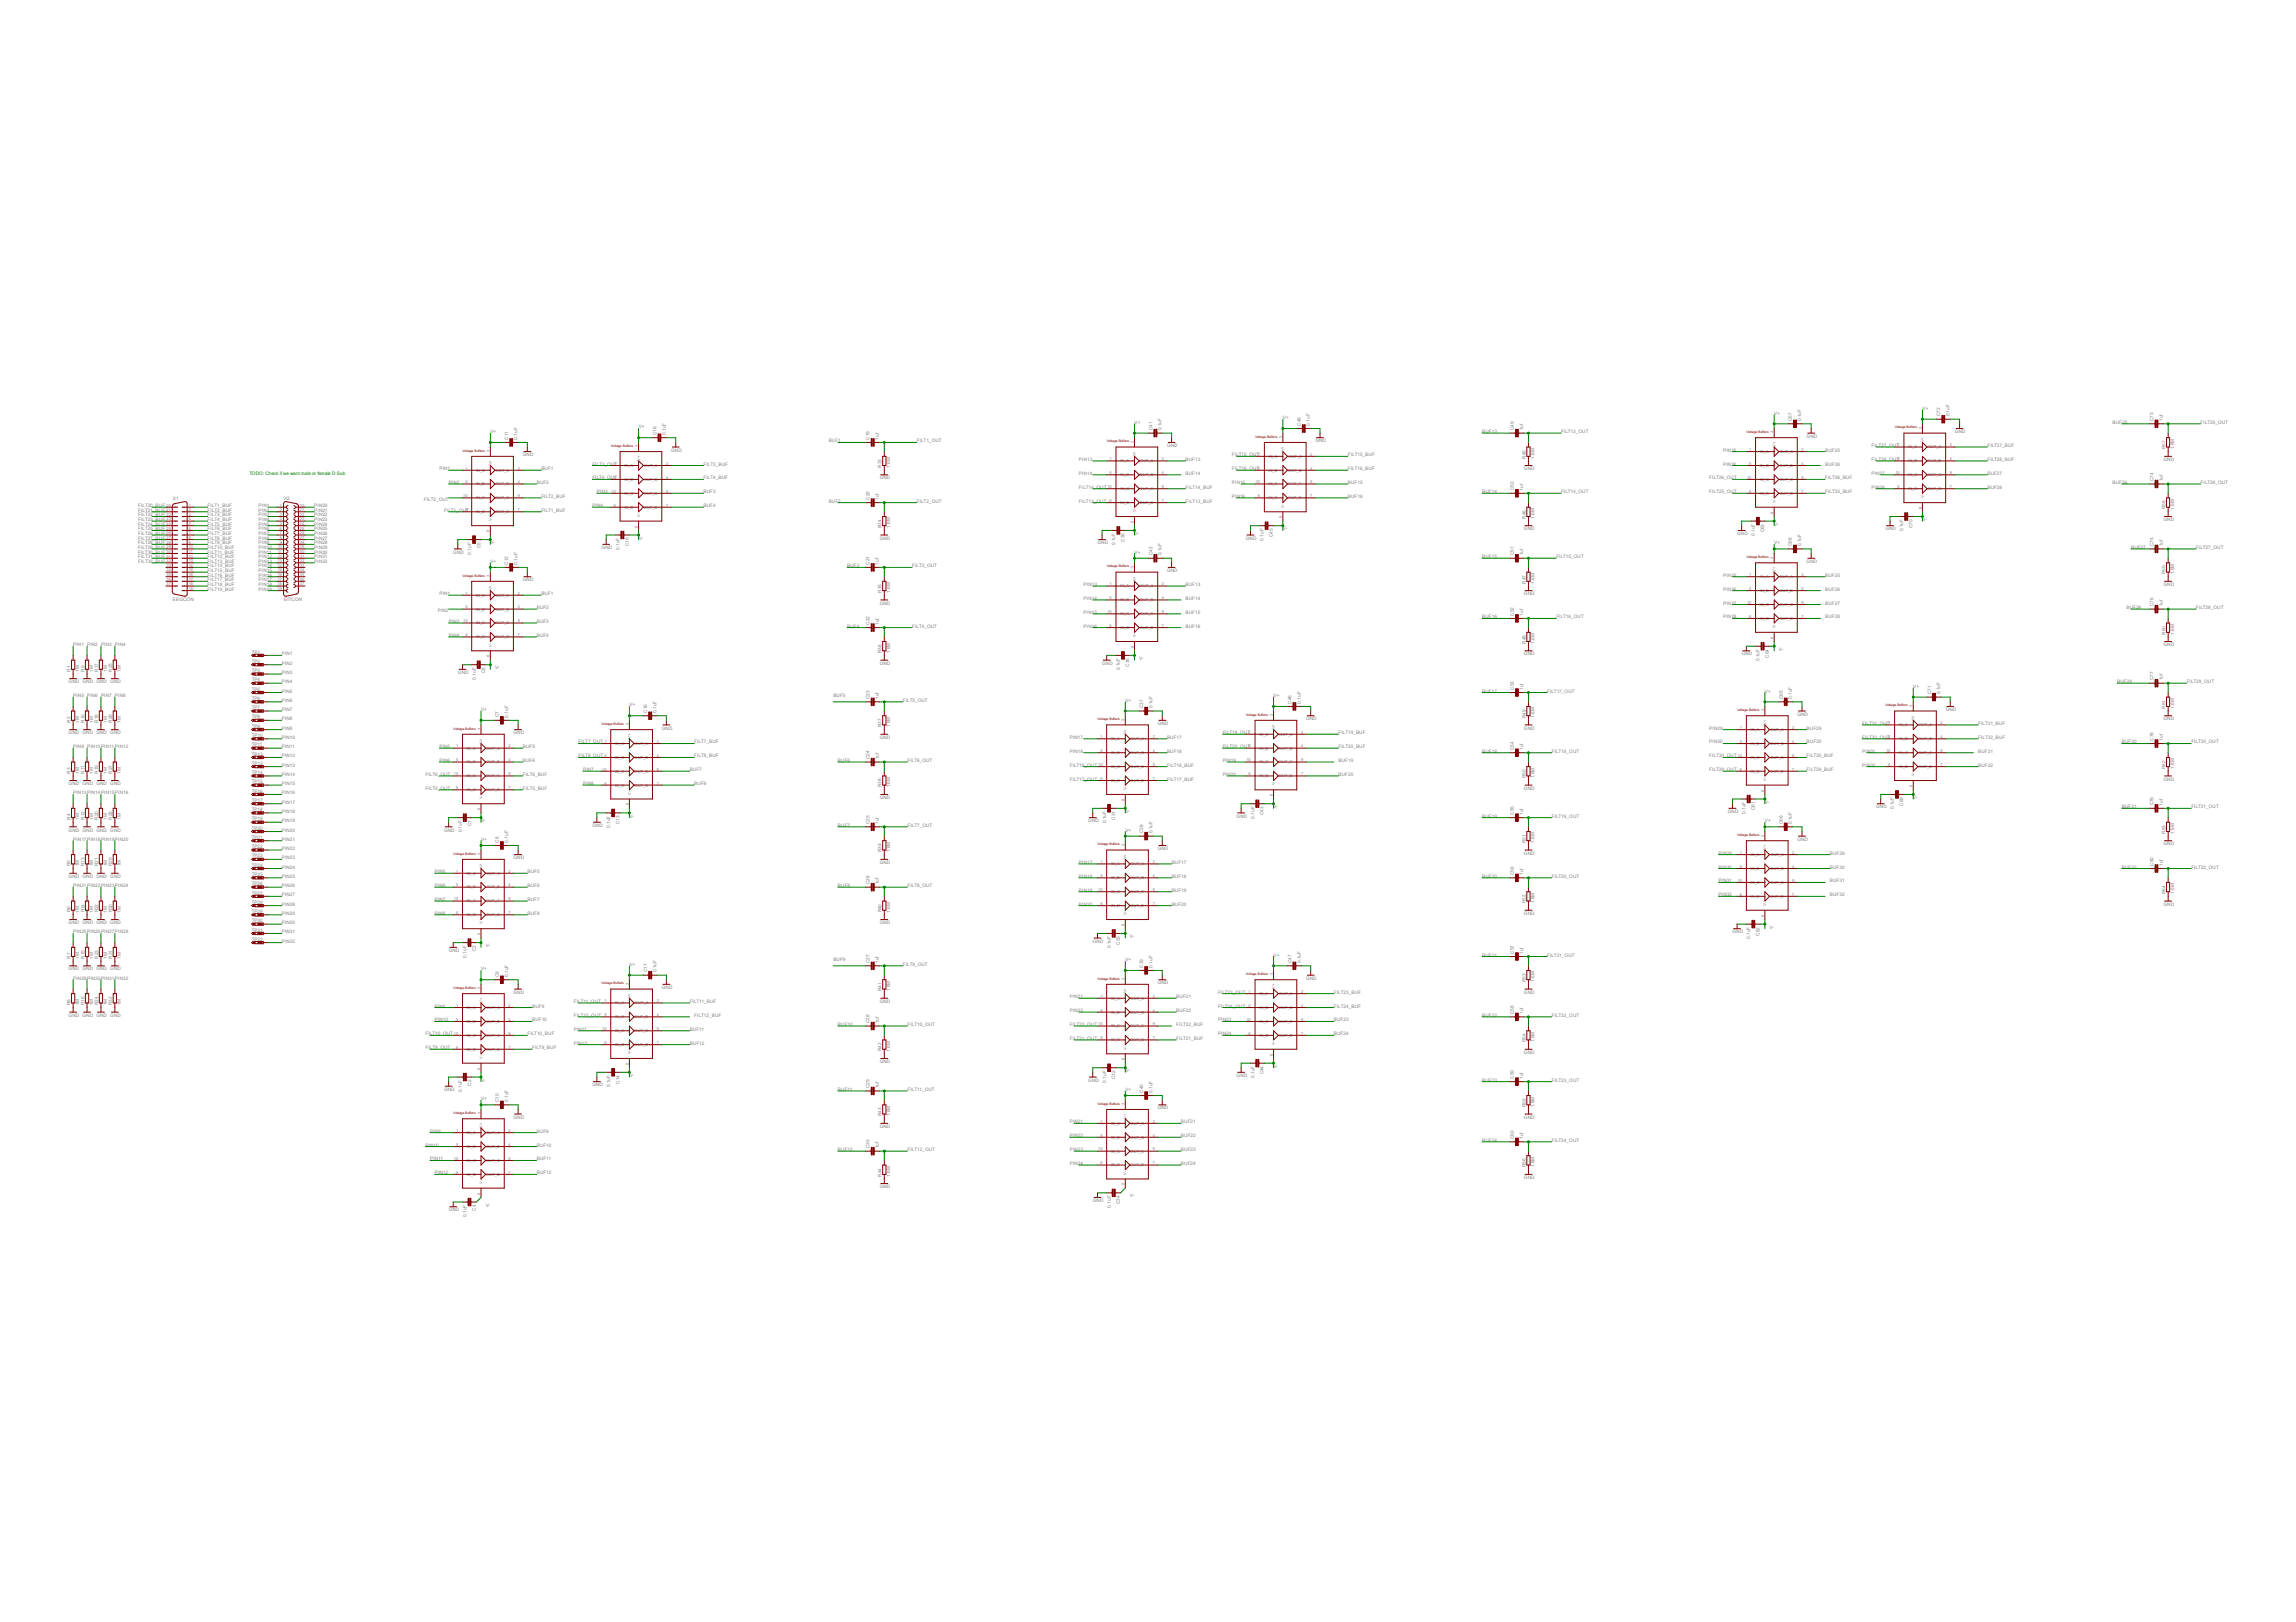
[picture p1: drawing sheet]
<svg xmlns="http://www.w3.org/2000/svg" width="297mm" height="210mm" viewBox="0 0 297 210" stroke-linecap="round" stroke-linejoin="round" font-family="sans-serif">
<defs><g id="words">
<g font-size=".7" fill="#808080">
<text x="229.5" y="53.7">V+</text>
<text x="248.7" y="53.1">V+</text>
<text x="251" y="53.9" transform="rotate(-90 251 53.9)">C72</text>
<text x="252.2" y="53.9" transform="rotate(-90 252.2 53.9)">0.1uF</text>
<text x="63.4" y="56">V+</text>
<text x="65.7" y="56.9" transform="rotate(-90 65.7 56.9)">C11</text>
<text x="66.9" y="56.9" transform="rotate(-90 66.9 56.9)">0.1uF</text>
<text x="67.6" y="59">GND</text>
<text x="82.6" y="55.4">V+</text>
<text x="84.9" y="56.3" transform="rotate(-90 84.9 56.3)">C18</text>
<text x="86.1" y="56.3" transform="rotate(-90 86.1 56.3)">0.1uF</text>
<text x="86.8" y="58.4">GND</text>
<text x="107.2" y="57.2">BUF1</text>
<text x="112.5" y="56.9" transform="rotate(-90 112.5 56.9)">C19</text>
<text x="113.7" y="56.9" transform="rotate(-90 113.7 56.9)">1uf</text>
<text x="118.6" y="57.2">FILT1_OUT</text>
<text x="139.6" y="59.6">PIN13</text>
<text x="146.8" y="54.8">V+</text>
<text x="149.1" y="55.7" transform="rotate(-90 149.1 55.7)">C41</text>
<text x="150.3" y="55.7" transform="rotate(-90 150.3 55.7)">0.1uF</text>
<text x="151" y="57.8">GND</text>
<text x="153.4" y="59.6">BUF13</text>
<text x="159.4" y="59">FILT15_OUT</text>
<text x="166" y="54.2">V+</text>
<text x="168.3" y="55.1" transform="rotate(-90 168.3 55.1)">C48</text>
<text x="169.5" y="55.1" transform="rotate(-90 169.5 55.1)">0.1uF</text>
<text x="170.2" y="57.2">GND</text>
<text x="174.4" y="59">FILT15_BUF</text>
<text x="191.8" y="56">BUF13</text>
<text x="195.9" y="55.7" transform="rotate(-90 195.9 55.7)">C49</text>
<text x="197.1" y="55.7" transform="rotate(-90 197.1 55.7)">1uf</text>
<text x="197.4" y="59.3" transform="rotate(-90 197.4 59.3)">R45</text>
<text x="198.5" y="59.3" transform="rotate(-90 198.5 59.3)">1.6M</text>
<text x="202" y="56">FILT13_OUT</text>
<text x="222.9" y="58.4">PIN25</text>
<text x="231.8" y="54.5" transform="rotate(-90 231.8 54.5)">C67</text>
<text x="233" y="54.5" transform="rotate(-90 233 54.5)">0.1uF</text>
<text x="233.7" y="56.6">GND</text>
<text x="236.1" y="58.4">BUF25</text>
<text x="242.1" y="57.8">FILT27_OUT</text>
<text x="242.1" y="59.6">FILT28_OUT</text>
<text x="252.9" y="56">GND</text>
<text x="257.1" y="57.8">FILT27_BUF</text>
<text x="257.1" y="59.6">FILT28_BUF</text>
<text x="273.3" y="54.8">BUF25</text>
<text x="278.6" y="54.5" transform="rotate(-90 278.6 54.5)">C73</text>
<text x="279.8" y="54.5" transform="rotate(-90 279.8 54.5)">1uf</text>
<text x="279.9" y="59.6">GND</text>
<text x="280.1" y="58.1" transform="rotate(-90 280.1 58.1)">R57</text>
<text x="281.3" y="58.1" transform="rotate(-90 281.3 58.1)">1.6M</text>
<text x="284.7" y="54.8">FILT25_OUT</text>
<text x="17.9" y="65.6">FILT20_BUF</text>
<text x="22.4" y="64.7">X1</text>
<text x="26.9" y="65.6">FILT1_BUF</text>
<text x="33.5" y="65.6">PIN1</text>
<text x="36.8" y="64.7">X2</text>
<text x="40.7" y="65.6">PIN20</text>
<text x="54.8" y="64.9">FILT2_OUT</text>
<text x="56.8" y="60.8">PIN1</text>
<text x="58" y="62.6">PIN2</text>
<text x="69.4" y="62.6">BUF2</text>
<text x="70" y="60.8">BUF1</text>
<text x="70" y="64.4">FILT2_BUF</text>
<text x="76.6" y="65.6">PIN4</text>
<text x="76.6" y="62">FILT4_OUT</text>
<text x="76.6" y="60.2">FILT3_OUT</text>
<text x="77.2" y="63.8">PIN3</text>
<text x="91" y="60.2">FILT3_BUF</text>
<text x="91" y="62">FILT4_BUF</text>
<text x="91" y="63.8">BUF3</text>
<text x="91" y="65.6">BUF4</text>
<text x="107.2" y="65">BUF2</text>
<text x="112.5" y="64.7" transform="rotate(-90 112.5 64.7)">C20</text>
<text x="113.7" y="64.7" transform="rotate(-90 113.7 64.7)">1uf</text>
<text x="113.8" y="62">GND</text>
<text x="114" y="60.5" transform="rotate(-90 114 60.5)">R33</text>
<text x="115.2" y="60.5" transform="rotate(-90 115.2 60.5)">1.6M</text>
<text x="118.6" y="65">FILT2_OUT</text>
<text x="139.6" y="61.4">PIN14</text>
<text x="139.6" y="65">FILT13_OUT</text>
<text x="139.6" y="63.2">FILT14_OUT</text>
<text x="153.4" y="65">FILT13_BUF</text>
<text x="153.4" y="63.2">FILT14_BUF</text>
<text x="153.4" y="61.4">BUF14</text>
<text x="159.4" y="62.6">PIN15</text>
<text x="159.4" y="64.4">PIN16</text>
<text x="159.4" y="60.8">FILT16_OUT</text>
<text x="174.4" y="60.8">FILT16_BUF</text>
<text x="174.4" y="62.6">BUF15</text>
<text x="174.4" y="64.4">BUF16</text>
<text x="191.8" y="63.8">BUF14</text>
<text x="195.9" y="63.5" transform="rotate(-90 195.9 63.5)">C50</text>
<text x="197.1" y="63.5" transform="rotate(-90 197.1 63.5)">1uf</text>
<text x="197.2" y="60.8">GND</text>
<text x="202" y="63.8">FILT14_OUT</text>
<text x="221.1" y="63.8">FILT25_OUT</text>
<text x="221.1" y="62">FILT26_OUT</text>
<text x="222.9" y="60.2">PIN26</text>
<text x="236.1" y="63.8">FILT25_BUF</text>
<text x="236.1" y="62">FILT26_BUF</text>
<text x="236.1" y="60.2">BUF26</text>
<text x="242.1" y="61.4">PIN27</text>
<text x="242.1" y="63.2">PIN28</text>
<text x="257.1" y="61.4">BUF27</text>
<text x="257.1" y="63.2">BUF28</text>
<text x="273.3" y="62.6">BUF26</text>
<text x="278.6" y="62.3" transform="rotate(-90 278.6 62.3)">C74</text>
<text x="279.8" y="62.3" transform="rotate(-90 279.8 62.3)">1uf</text>
<text x="280.1" y="65.9" transform="rotate(-90 280.1 65.9)">R58</text>
<text x="281.3" y="65.9" transform="rotate(-90 281.3 65.9)">1.6M</text>
<text x="284.7" y="62.6">FILT26_OUT</text>
<text x="17.9" y="66.2">FILT21_BUF</text>
<text x="17.9" y="66.8">FILT22_BUF</text>
<text x="17.9" y="67.4">FILT23_BUF</text>
<text x="17.9" y="68">FILT24_BUF</text>
<text x="17.9" y="68.6">FILT25_BUF</text>
<text x="17.9" y="69.2">FILT26_BUF</text>
<text x="17.9" y="69.8">FILT27_BUF</text>
<text x="17.9" y="70.4">FILT28_BUF</text>
<text x="17.9" y="71">FILT29_BUF</text>
<text x="17.9" y="71.6">FILT30_BUF</text>
<text x="26.9" y="66.2">FILT2_BUF</text>
<text x="26.9" y="66.8">FILT3_BUF</text>
<text x="26.9" y="67.4">FILT4_BUF</text>
<text x="26.9" y="68">FILT5_BUF</text>
<text x="26.9" y="68.6">FILT6_BUF</text>
<text x="26.9" y="69.2">FILT7_BUF</text>
<text x="26.9" y="69.8">FILT8_BUF</text>
<text x="26.9" y="70.4">FILT9_BUF</text>
<text x="26.9" y="71">FILT10_BUF</text>
<text x="26.9" y="71.6">FILT11_BUF</text>
<text x="33.5" y="66.2">PIN2</text>
<text x="33.5" y="66.8">PIN3</text>
<text x="33.5" y="67.4">PIN4</text>
<text x="33.5" y="68">PIN5</text>
<text x="33.5" y="68.6">PIN6</text>
<text x="33.5" y="69.2">PIN7</text>
<text x="33.5" y="69.8">PIN8</text>
<text x="33.5" y="70.4">PIN9</text>
<text x="33.5" y="71">PIN10</text>
<text x="33.5" y="71.6">PIN11</text>
<text x="40.7" y="66.2">PIN21</text>
<text x="40.7" y="66.8">PIN22</text>
<text x="40.7" y="67.4">PIN23</text>
<text x="40.7" y="68">PIN24</text>
<text x="40.7" y="68.6">PIN25</text>
<text x="40.7" y="69.2">PIN26</text>
<text x="40.7" y="69.8">PIN27</text>
<text x="40.7" y="70.4">PIN28</text>
<text x="40.7" y="71">PIN29</text>
<text x="40.7" y="71.6">PIN30</text>
<text x="57.4" y="66.2">FILT1_OUT</text>
<text x="58.6" y="71.6">GND</text>
<text x="60.9" y="71.8" transform="rotate(-90 60.9 71.8)">0.1uF</text>
<text x="62.1" y="71" transform="rotate(-90 62.1 71)">C5</text>
<text x="63.4" y="70.4">V-</text>
<text x="70" y="66.2">FILT1_BUF</text>
<text x="77.8" y="71">GND</text>
<text x="80.1" y="71.2" transform="rotate(-90 80.1 71.2)">0.1uF</text>
<text x="81.3" y="70.7" transform="rotate(-90 81.3 70.7)">C15</text>
<text x="82.6" y="69.8">V-</text>
<text x="113.8" y="69.8">GND</text>
<text x="114" y="68.3" transform="rotate(-90 114 68.3)">R34</text>
<text x="115.2" y="68.3" transform="rotate(-90 115.2 68.3)">1.6M</text>
<text x="142" y="70.4">GND</text>
<text x="144.3" y="70.6" transform="rotate(-90 144.3 70.6)">0.1uF</text>
<text x="145.5" y="70.1" transform="rotate(-90 145.5 70.1)">C35</text>
<text x="146.8" y="71.6">V+</text>
<text x="146.8" y="69.2">V-</text>
<text x="149.1" y="71.9" transform="rotate(-90 149.1 71.9)">C42</text>
<text x="150.3" y="71.9" transform="rotate(-90 150.3 71.9)">0.1uF</text>
<text x="161.2" y="69.8">GND</text>
<text x="163.5" y="70" transform="rotate(-90 163.5 70)">0.1uF</text>
<text x="164.7" y="69.5" transform="rotate(-90 164.7 69.5)">C45</text>
<text x="166" y="68.6">V-</text>
<text x="195.9" y="71.9" transform="rotate(-90 195.9 71.9)">C51</text>
<text x="197.1" y="71.9" transform="rotate(-90 197.1 71.9)">1uf</text>
<text x="197.2" y="68.6">GND</text>
<text x="197.4" y="67.1" transform="rotate(-90 197.4 67.1)">R46</text>
<text x="198.5" y="67.1" transform="rotate(-90 198.5 67.1)">1.6M</text>
<text x="224.7" y="69.2">GND</text>
<text x="227" y="69.4" transform="rotate(-90 227 69.4)">0.1uF</text>
<text x="228.2" y="68.9" transform="rotate(-90 228.2 68.9)">C63</text>
<text x="229.5" y="70.4">V+</text>
<text x="229.5" y="68">V-</text>
<text x="231.8" y="70.7" transform="rotate(-90 231.8 70.7)">C68</text>
<text x="233" y="70.7" transform="rotate(-90 233 70.7)">0.1uF</text>
<text x="243.9" y="68.6">GND</text>
<text x="246.2" y="68.8" transform="rotate(-90 246.2 68.8)">0.1uF</text>
<text x="247.4" y="68.3" transform="rotate(-90 247.4 68.3)">C70</text>
<text x="248.7" y="67.4">V-</text>
<text x="275.7" y="71">BUF27</text>
<text x="278.6" y="70.7" transform="rotate(-90 278.6 70.7)">C75</text>
<text x="279.8" y="70.7" transform="rotate(-90 279.8 70.7)">1uf</text>
<text x="279.9" y="67.4">GND</text>
<text x="284.1" y="71">FILT27_OUT</text>
<text x="17.9" y="72.2">FILT31_BUF</text>
<text x="17.9" y="72.8">FILT32_BUF</text>
<text x="22.4" y="77.8">EEGCON</text>
<text x="26.9" y="72.2">FILT12_BUF</text>
<text x="26.9" y="72.8">FILT13_BUF</text>
<text x="26.9" y="73.4">FILT14_BUF</text>
<text x="26.9" y="74">FILT15_BUF</text>
<text x="26.9" y="74.6">FILT16_BUF</text>
<text x="26.9" y="75.2">FILT17_BUF</text>
<text x="26.9" y="75.8">FILT18_BUF</text>
<text x="26.9" y="76.4">FILT19_BUF</text>
<text x="33.5" y="72.2">PIN12</text>
<text x="33.5" y="72.8">PIN13</text>
<text x="33.5" y="73.4">PIN14</text>
<text x="33.5" y="74">PIN15</text>
<text x="33.5" y="74.6">PIN16</text>
<text x="33.5" y="75.2">PIN17</text>
<text x="33.5" y="75.8">PIN18</text>
<text x="33.5" y="76.4">PIN19</text>
<text x="36.8" y="77.8">EITCON</text>
<text x="40.7" y="72.2">PIN31</text>
<text x="40.7" y="72.8">PIN32</text>
<text x="56.8" y="77">PIN1</text>
<text x="63.4" y="72.8">V+</text>
<text x="65.7" y="73.1" transform="rotate(-90 65.7 73.1)">C12</text>
<text x="66.9" y="73.1" transform="rotate(-90 66.9 73.1)">0.1uF</text>
<text x="67.6" y="75.2">GND</text>
<text x="70" y="77">BUF1</text>
<text x="109.6" y="73.4">BUF3</text>
<text x="112.5" y="73.1" transform="rotate(-90 112.5 73.1)">C21</text>
<text x="113.7" y="73.1" transform="rotate(-90 113.7 73.1)">1uf</text>
<text x="114" y="76.7" transform="rotate(-90 114 76.7)">R35</text>
<text x="115.2" y="76.7" transform="rotate(-90 115.2 76.7)">1.6M</text>
<text x="118" y="73.4">FILT3_OUT</text>
<text x="140.2" y="75.8">PIN13</text>
<text x="140.2" y="77.6">PIN14</text>
<text x="151" y="74">GND</text>
<text x="153.4" y="75.8">BUF13</text>
<text x="153.4" y="77.6">BUF14</text>
<text x="191.8" y="72.2">BUF15</text>
<text x="197.2" y="77">GND</text>
<text x="197.4" y="75.5" transform="rotate(-90 197.4 75.5)">R47</text>
<text x="198.5" y="75.5" transform="rotate(-90 198.5 75.5)">1.6M</text>
<text x="201.4" y="72.2">FILT15_OUT</text>
<text x="222.9" y="74.6">PIN25</text>
<text x="222.9" y="76.4">PIN26</text>
<text x="233.7" y="72.8">GND</text>
<text x="236.1" y="74.6">BUF25</text>
<text x="236.1" y="76.4">BUF26</text>
<text x="279.9" y="75.8">GND</text>
<text x="280.1" y="74.3" transform="rotate(-90 280.1 74.3)">R59</text>
<text x="281.3" y="74.3" transform="rotate(-90 281.3 74.3)">1.6M</text>
<text x="9.5" y="83.6">PIN1 PIN2 PIN3 PIN4</text>
<text x="56.6" y="79.3">PIN2</text>
<text x="58" y="80.6">PIN3</text>
<text x="58" y="82.4">PIN4</text>
<text x="69.4" y="78.8">BUF2</text>
<text x="69.4" y="80.6">BUF3</text>
<text x="69.4" y="82.4">BUF4</text>
<text x="109.6" y="81.2">BUF4</text>
<text x="112.5" y="80.9" transform="rotate(-90 112.5 80.9)">C22</text>
<text x="113.7" y="80.9" transform="rotate(-90 113.7 80.9)">1uf</text>
<text x="113.8" y="78.2">GND</text>
<text x="118" y="81.2">FILT4_OUT</text>
<text x="140.2" y="79.4">PIN15</text>
<text x="140.2" y="81.2">PIN16</text>
<text x="153.4" y="79.4">BUF15</text>
<text x="153.4" y="81.2">BUF16</text>
<text x="191.8" y="80">BUF16</text>
<text x="195.9" y="79.7" transform="rotate(-90 195.9 79.7)">C52</text>
<text x="197.1" y="79.7" transform="rotate(-90 197.1 79.7)">1uf</text>
<text x="197.4" y="83.3" transform="rotate(-90 197.4 83.3)">R48</text>
<text x="198.5" y="83.3" transform="rotate(-90 198.5 83.3)">1.6M</text>
<text x="201.4" y="80">FILT16_OUT</text>
<text x="222.9" y="78.2">PIN27</text>
<text x="222.9" y="80">PIN28</text>
<text x="236.1" y="78.2">BUF27</text>
<text x="236.1" y="80">BUF28</text>
<text x="275.1" y="78.8">BUF28</text>
<text x="278.6" y="78.5" transform="rotate(-90 278.6 78.5)">C76</text>
<text x="279.8" y="78.5" transform="rotate(-90 279.8 78.5)">1uf</text>
<text x="279.9" y="83.6">GND</text>
<text x="280.1" y="82.1" transform="rotate(-90 280.1 82.1)">R60</text>
<text x="281.3" y="82.1" transform="rotate(-90 281.3 82.1)">1.6M</text>
<text x="284.1" y="78.8">FILT28_OUT</text>
<text x="8.9" y="88.4">GND GND GND GND</text>
<text x="9.1" y="86.9" transform="rotate(-90 9.1 86.9)">R1</text>
<text x="10.2" y="86.9" transform="rotate(-90 10.2 86.9)">1M</text>
<text x="10.9" y="86.9" transform="rotate(-90 10.9 86.9)">R9</text>
<text x="12" y="86.9" transform="rotate(-90 12 86.9)">1M</text>
<text x="12.7" y="86.9" transform="rotate(-90 12.7 86.9)">R17</text>
<text x="13.8" y="86.9" transform="rotate(-90 13.8 86.9)">1M</text>
<text x="14.5" y="86.9" transform="rotate(-90 14.5 86.9)">R25</text>
<text x="15.6" y="86.9" transform="rotate(-90 15.6 86.9)">1M</text>
<text x="32.6" y="84.6">TP1</text>
<text x="32.6" y="85.8">TP2</text>
<text x="32.6" y="87">TP3</text>
<text x="32.6" y="88.2">TP4</text>
<text x="32.6" y="89.4">TP5</text>
<text x="36.5" y="84.8">PIN1</text>
<text x="36.5" y="86">PIN2</text>
<text x="36.5" y="87.2">PIN3</text>
<text x="36.5" y="88.4">PIN4</text>
<text x="36.5" y="89.6">PIN5</text>
<text x="59.2" y="87.2">GND</text>
<text x="61.5" y="87.9" transform="rotate(-90 61.5 87.9)">0.1uF</text>
<text x="62.7" y="87.2" transform="rotate(-90 62.7 87.2)">C6</text>
<text x="64" y="86.6">V-</text>
<text x="113.8" y="86">GND</text>
<text x="114" y="84.5" transform="rotate(-90 114 84.5)">R36</text>
<text x="115.2" y="84.5" transform="rotate(-90 115.2 84.5)">1.6M</text>
<text x="142.6" y="86">GND</text>
<text x="144.9" y="86.7" transform="rotate(-90 144.9 86.7)">0.1uF</text>
<text x="146.1" y="86.3" transform="rotate(-90 146.1 86.3)">C36</text>
<text x="147.4" y="85.4">V-</text>
<text x="191.8" y="89.6">BUF17</text>
<text x="195.9" y="89.2" transform="rotate(-90 195.9 89.2)">C53</text>
<text x="197.1" y="89.3" transform="rotate(-90 197.1 89.3)">1uf</text>
<text x="197.2" y="84.8">GND</text>
<text x="200.2" y="89.6">FILT17_OUT</text>
<text x="225.3" y="84.8">GND</text>
<text x="227.6" y="85.6" transform="rotate(-90 227.6 85.6)">0.1uF</text>
<text x="228.3" y="89.6">V+</text>
<text x="228.8" y="85.1" transform="rotate(-90 228.8 85.1)">C64</text>
<text x="230.1" y="84.2">V-</text>
<text x="247.5" y="89">V+</text>
<text x="249.8" y="89.8" transform="rotate(-90 249.8 89.8)">C71</text>
<text x="251" y="89.9" transform="rotate(-90 251 89.9)">0.1uF</text>
<text x="273.9" y="88.4">BUF29</text>
<text x="278.6" y="88.1" transform="rotate(-90 278.6 88.1)">C77</text>
<text x="279.8" y="88.1" transform="rotate(-90 279.8 88.1)">1uf</text>
<text x="282.9" y="88.4">FILT29_OUT</text>
<text x="8.9" y="95">GND GND GND GND</text>
<text x="9.1" y="93.5" transform="rotate(-90 9.1 93.5)">R2</text>
<text x="9.5" y="90.2">PIN5 PIN6 PIN7 PIN8</text>
<text x="10.2" y="93.5" transform="rotate(-90 10.2 93.5)">1M</text>
<text x="10.9" y="93.5" transform="rotate(-90 10.9 93.5)">R10</text>
<text x="12" y="93.5" transform="rotate(-90 12 93.5)">1M</text>
<text x="12.7" y="93.5" transform="rotate(-90 12.7 93.5)">R18</text>
<text x="13.8" y="93.5" transform="rotate(-90 13.8 93.5)">1M</text>
<text x="14.5" y="93.5" transform="rotate(-90 14.5 93.5)">R26</text>
<text x="15.6" y="93.5" transform="rotate(-90 15.6 93.5)">1M</text>
<text x="32.6" y="90.6">TP6</text>
<text x="32.6" y="91.8">TP7</text>
<text x="32.6" y="93">TP8</text>
<text x="32.6" y="94.2">TP9</text>
<text x="32.6" y="95.4">TP10</text>
<text x="36.5" y="90.8">PIN6</text>
<text x="36.5" y="92">PIN7</text>
<text x="36.5" y="93.2">PIN8</text>
<text x="36.5" y="94.4">PIN9</text>
<text x="36.5" y="95.6">PIN10</text>
<text x="62.2" y="92">V+</text>
<text x="64.5" y="92.8" transform="rotate(-90 64.5 92.8)">C7</text>
<text x="65.7" y="92.9" transform="rotate(-90 65.7 92.9)">0.1uF</text>
<text x="66.4" y="95">GND</text>
<text x="81.4" y="91.4">V+</text>
<text x="83.7" y="92.2" transform="rotate(-90 83.7 92.2)">C16</text>
<text x="84.9" y="92.3" transform="rotate(-90 84.9 92.3)">0.1uF</text>
<text x="85.6" y="94.4">GND</text>
<text x="107.8" y="90.2">BUF5</text>
<text x="112.5" y="90.4" transform="rotate(-90 112.5 90.4)">C23</text>
<text x="113.7" y="90.5" transform="rotate(-90 113.7 90.5)">1uf</text>
<text x="113.8" y="95.6">GND</text>
<text x="114" y="94.1" transform="rotate(-90 114 94.1)">R37</text>
<text x="115.2" y="94.1" transform="rotate(-90 115.2 94.1)">1.6M</text>
<text x="116.8" y="90.8">FILT5_OUT</text>
<text x="138.4" y="95.6">PIN17</text>
<text x="145.6" y="90.8">V+</text>
<text x="147.9" y="91.6" transform="rotate(-90 147.9 91.6)">C37</text>
<text x="149.1" y="91.7" transform="rotate(-90 149.1 91.7)">0.1uF</text>
<text x="149.8" y="93.8">GND</text>
<text x="151" y="95.6">BUF17</text>
<text x="158.2" y="95">FILT19_OUT</text>
<text x="164.8" y="90.2">V+</text>
<text x="167.1" y="91" transform="rotate(-90 167.1 91)">C46</text>
<text x="168.3" y="91.1" transform="rotate(-90 168.3 91.1)">0.1uF</text>
<text x="169" y="93.2">GND</text>
<text x="173.2" y="95">FILT19_BUF</text>
<text x="197.2" y="94.4">GND</text>
<text x="197.4" y="92.9" transform="rotate(-90 197.4 92.9)">R49</text>
<text x="198.5" y="92.9" transform="rotate(-90 198.5 92.9)">1.6M</text>
<text x="221.1" y="94.4">PIN29</text>
<text x="230.6" y="90.4" transform="rotate(-90 230.6 90.4)">C65</text>
<text x="231.8" y="90.5" transform="rotate(-90 231.8 90.5)">0.1uF</text>
<text x="232.5" y="92.6">GND</text>
<text x="233.7" y="94.4">BUF29</text>
<text x="240.9" y="93.8">FILT31_OUT</text>
<text x="240.9" y="95.6">FILT32_OUT</text>
<text x="251.7" y="92">GND</text>
<text x="255.9" y="93.8">FILT31_BUF</text>
<text x="255.9" y="95.6">FILT32_BUF</text>
<text x="278.6" y="95.8" transform="rotate(-90 278.6 95.8)">C78</text>
<text x="279.8" y="95.9" transform="rotate(-90 279.8 95.9)">1uf</text>
<text x="279.9" y="93.2">GND</text>
<text x="280.1" y="91.7" transform="rotate(-90 280.1 91.7)">R61</text>
<text x="281.3" y="91.7" transform="rotate(-90 281.3 91.7)">1.6M</text>
<text x="8.9" y="101.6">GND GND GND GND</text>
<text x="9.1" y="100.1" transform="rotate(-90 9.1 100.1)">R3</text>
<text x="9.5" y="96.8">PIN9 PIN10PIN11 PIN12</text>
<text x="10.2" y="100.1" transform="rotate(-90 10.2 100.1)">1M</text>
<text x="10.9" y="100.1" transform="rotate(-90 10.9 100.1)">R11</text>
<text x="12" y="100.1" transform="rotate(-90 12 100.1)">1M</text>
<text x="12.7" y="100.1" transform="rotate(-90 12.7 100.1)">R19</text>
<text x="13.8" y="100.1" transform="rotate(-90 13.8 100.1)">1M</text>
<text x="14.5" y="100.1" transform="rotate(-90 14.5 100.1)">R27</text>
<text x="15.6" y="100.1" transform="rotate(-90 15.6 100.1)">1M</text>
<text x="32.6" y="96.6">TP11</text>
<text x="32.6" y="97.8">TP12</text>
<text x="32.6" y="99">TP13</text>
<text x="32.6" y="100.2">TP14</text>
<text x="32.6" y="101.4">TP15</text>
<text x="36.5" y="96.8">PIN11</text>
<text x="36.5" y="98">PIN12</text>
<text x="36.5" y="99.2">PIN13</text>
<text x="36.5" y="100.4">PIN14</text>
<text x="36.5" y="101.6">PIN15</text>
<text x="55" y="100.4">FILT6_OUT</text>
<text x="56.8" y="96.8">PIN5</text>
<text x="56.8" y="98.6">PIN6</text>
<text x="67.6" y="100.4">FILT6_BUF</text>
<text x="67.6" y="96.8">BUF5</text>
<text x="67.6" y="98.6">BUF6</text>
<text x="74.8" y="98">FILT8_OUT</text>
<text x="74.8" y="96.2">FILT7_OUT</text>
<text x="75.4" y="99.8">PIN7</text>
<text x="75.4" y="101.6">PIN8</text>
<text x="89.2" y="99.8">BUF7</text>
<text x="89.8" y="96.2">FILT7_BUF</text>
<text x="89.8" y="98">FILT8_BUF</text>
<text x="89.8" y="101.6">BUF8</text>
<text x="108.4" y="98.6">BUF6</text>
<text x="112.5" y="98.2" transform="rotate(-90 112.5 98.2)">C24</text>
<text x="113.7" y="98.3" transform="rotate(-90 113.7 98.3)">1uf</text>
<text x="114" y="101.9" transform="rotate(-90 114 101.9)">R38</text>
<text x="115.2" y="101.9" transform="rotate(-90 115.2 101.9)">1.6M</text>
<text x="117.4" y="98.6">FILT6_OUT</text>
<text x="138.4" y="97.4">PIN18</text>
<text x="138.4" y="101">FILT17_OUT</text>
<text x="138.4" y="99.2">FILT18_OUT</text>
<text x="151" y="101">FILT17_BUF</text>
<text x="151" y="99.2">FILT18_BUF</text>
<text x="151" y="97.4">BUF18</text>
<text x="158.2" y="98.6">PIN19</text>
<text x="158.2" y="100.4">PIN20</text>
<text x="158.2" y="96.8">FILT20_OUT</text>
<text x="173.2" y="96.8">FILT20_BUF</text>
<text x="173.2" y="98.6">BUF19</text>
<text x="173.2" y="100.4">BUF20</text>
<text x="191.8" y="97.4">BUF18</text>
<text x="195.9" y="97" transform="rotate(-90 195.9 97)">C54</text>
<text x="197.1" y="97.1" transform="rotate(-90 197.1 97.1)">1uf</text>
<text x="197.4" y="100.7" transform="rotate(-90 197.4 100.7)">R50</text>
<text x="198.5" y="100.7" transform="rotate(-90 198.5 100.7)">1.6M</text>
<text x="200.8" y="97.4">FILT18_OUT</text>
<text x="221.1" y="96.2">PIN30</text>
<text x="221.1" y="99.8">FILT29_OUT</text>
<text x="221.1" y="98">FILT30_OUT</text>
<text x="233.7" y="99.8">FILT29_BUF</text>
<text x="233.7" y="98">FILT30_BUF</text>
<text x="233.7" y="96.2">BUF30</text>
<text x="240.9" y="97.4">PIN31</text>
<text x="240.9" y="99.2">PIN32</text>
<text x="255.9" y="97.4">BUF31</text>
<text x="255.9" y="99.2">BUF32</text>
<text x="274.5" y="96.2">BUF30</text>
<text x="279.9" y="101">GND</text>
<text x="280.1" y="99.5" transform="rotate(-90 280.1 99.5)">R62</text>
<text x="281.3" y="99.5" transform="rotate(-90 281.3 99.5)">1.6M</text>
<text x="283.5" y="96.2">FILT30_OUT</text>
<text x="8.9" y="107.6">GND GND GND GND</text>
<text x="9.1" y="106.1" transform="rotate(-90 9.1 106.1)">R4</text>
<text x="9.5" y="102.8">PIN13PIN14PIN15PIN16</text>
<text x="10.2" y="106.1" transform="rotate(-90 10.2 106.1)">1M</text>
<text x="10.9" y="106.1" transform="rotate(-90 10.9 106.1)">R12</text>
<text x="12" y="106.1" transform="rotate(-90 12 106.1)">1M</text>
<text x="12.7" y="106.1" transform="rotate(-90 12.7 106.1)">R20</text>
<text x="13.8" y="106.1" transform="rotate(-90 13.8 106.1)">1M</text>
<text x="14.5" y="106.1" transform="rotate(-90 14.5 106.1)">R28</text>
<text x="15.6" y="106.1" transform="rotate(-90 15.6 106.1)">1M</text>
<text x="32.6" y="102.6">TP16</text>
<text x="32.6" y="103.8">TP17</text>
<text x="32.6" y="105">TP18</text>
<text x="32.6" y="106.2">TP19</text>
<text x="32.6" y="107.4">TP20</text>
<text x="36.5" y="102.8">PIN16</text>
<text x="36.5" y="104">PIN17</text>
<text x="36.5" y="105.2">PIN18</text>
<text x="36.5" y="106.4">PIN19</text>
<text x="36.5" y="107.6">PIN20</text>
<text x="55" y="102.2">FILT5_OUT</text>
<text x="57.4" y="107.6">GND</text>
<text x="59.7" y="107.7" transform="rotate(-90 59.7 107.7)">0.1uF</text>
<text x="60.9" y="106.9" transform="rotate(-90 60.9 106.9)">C1</text>
<text x="62.2" y="106.4">V-</text>
<text x="67.6" y="102.2">FILT5_BUF</text>
<text x="76.6" y="107">GND</text>
<text x="78.9" y="107.1" transform="rotate(-90 78.9 107.1)">0.1uF</text>
<text x="80.1" y="106.7" transform="rotate(-90 80.1 106.7)">C13</text>
<text x="81.4" y="105.8">V-</text>
<text x="108.4" y="107">BUF7</text>
<text x="112.5" y="106.6" transform="rotate(-90 112.5 106.6)">C25</text>
<text x="113.7" y="106.6" transform="rotate(-90 113.7 106.6)">1uf</text>
<text x="113.8" y="103.4">GND</text>
<text x="117.4" y="107">FILT7_OUT</text>
<text x="140.8" y="106.4">GND</text>
<text x="143.1" y="106.5" transform="rotate(-90 143.1 106.5)">0.1uF</text>
<text x="144.3" y="106.1" transform="rotate(-90 144.3 106.1)">C31</text>
<text x="145.6" y="107.6">V+</text>
<text x="145.6" y="105.2">V-</text>
<text x="147.9" y="107.8" transform="rotate(-90 147.9 107.8)">C38</text>
<text x="149.1" y="107.8" transform="rotate(-90 149.1 107.8)">0.1uF</text>
<text x="160" y="105.8">GND</text>
<text x="162.3" y="105.9" transform="rotate(-90 162.3 105.9)">0.1uF</text>
<text x="163.5" y="105.5" transform="rotate(-90 163.5 105.5)">C43</text>
<text x="164.8" y="104.6">V-</text>
<text x="191.8" y="105.8">BUF19</text>
<text x="195.9" y="105.4" transform="rotate(-90 195.9 105.4)">C55</text>
<text x="197.1" y="105.4" transform="rotate(-90 197.1 105.4)">1uf</text>
<text x="197.2" y="102.2">GND</text>
<text x="200.8" y="105.8">FILT19_OUT</text>
<text x="223.5" y="105.2">GND</text>
<text x="225.8" y="105.3" transform="rotate(-90 225.8 105.3)">0.1uF</text>
<text x="227" y="104.9" transform="rotate(-90 227 104.9)">C61</text>
<text x="228.3" y="106.4">V+</text>
<text x="228.3" y="104">V-</text>
<text x="230.6" y="106.6" transform="rotate(-90 230.6 106.6)">C66</text>
<text x="231.8" y="106.6" transform="rotate(-90 231.8 106.6)">0.1uF</text>
<text x="242.7" y="104.6">GND</text>
<text x="245" y="104.7" transform="rotate(-90 245 104.7)">0.1uF</text>
<text x="246.2" y="104.3" transform="rotate(-90 246.2 104.3)">C69</text>
<text x="247.5" y="103.4">V-</text>
<text x="274.5" y="104.6">BUF31</text>
<text x="278.6" y="104.2" transform="rotate(-90 278.6 104.2)">C79</text>
<text x="279.8" y="104.2" transform="rotate(-90 279.8 104.2)">1uf</text>
<text x="280.1" y="107.9" transform="rotate(-90 280.1 107.9)">R63</text>
<text x="281.3" y="107.9" transform="rotate(-90 281.3 107.9)">1.6M</text>
<text x="283.5" y="104.6">FILT31_OUT</text>
<text x="8.9" y="113.6">GND GND GND GND</text>
<text x="9.1" y="112.1" transform="rotate(-90 9.1 112.1)">R5</text>
<text x="9.5" y="108.8">PIN17PIN18PIN19PIN20</text>
<text x="10.2" y="112.1" transform="rotate(-90 10.2 112.1)">1M</text>
<text x="10.9" y="112.1" transform="rotate(-90 10.9 112.1)">R13</text>
<text x="12" y="112.1" transform="rotate(-90 12 112.1)">1M</text>
<text x="12.7" y="112.1" transform="rotate(-90 12.7 112.1)">R21</text>
<text x="13.8" y="112.1" transform="rotate(-90 13.8 112.1)">1M</text>
<text x="14.5" y="112.1" transform="rotate(-90 14.5 112.1)">R29</text>
<text x="15.6" y="112.1" transform="rotate(-90 15.6 112.1)">1M</text>
<text x="32.6" y="108.6">TP21</text>
<text x="32.6" y="109.8">TP22</text>
<text x="32.6" y="111">TP23</text>
<text x="32.6" y="112.2">TP24</text>
<text x="32.6" y="113.4">TP25</text>
<text x="36.5" y="108.8">PIN21</text>
<text x="36.5" y="110">PIN22</text>
<text x="36.5" y="111.2">PIN23</text>
<text x="36.5" y="112.4">PIN24</text>
<text x="36.5" y="113.6">PIN25</text>
<text x="56.2" y="113">PIN5</text>
<text x="62.2" y="108.8">V+</text>
<text x="64.5" y="109" transform="rotate(-90 64.5 109)">C8</text>
<text x="65.7" y="109" transform="rotate(-90 65.7 109)">0.1uF</text>
<text x="66.4" y="111.2">GND</text>
<text x="68.2" y="113">BUF5</text>
<text x="113.8" y="111.8">GND</text>
<text x="114" y="110.3" transform="rotate(-90 114 110.3)">R39</text>
<text x="115.2" y="110.3" transform="rotate(-90 115.2 110.3)">1.6M</text>
<text x="139.6" y="111.8">PIN17</text>
<text x="139.6" y="113.6">PIN18</text>
<text x="149.8" y="110">GND</text>
<text x="151.6" y="111.8">BUF17</text>
<text x="151.6" y="113.6">BUF18</text>
<text x="191.8" y="113.6">BUF20</text>
<text x="195.9" y="113.2" transform="rotate(-90 195.9 113.2)">C56</text>
<text x="197.1" y="113.2" transform="rotate(-90 197.1 113.2)">1uf</text>
<text x="197.2" y="110.6">GND</text>
<text x="197.4" y="109.1" transform="rotate(-90 197.4 109.1)">R51</text>
<text x="198.5" y="109.1" transform="rotate(-90 198.5 109.1)">1.6M</text>
<text x="200.8" y="113.6">FILT20_OUT</text>
<text x="222.3" y="110.6">PIN29</text>
<text x="222.3" y="112.4">PIN30</text>
<text x="232.5" y="108.8">GND</text>
<text x="236.7" y="110.6">BUF29</text>
<text x="236.7" y="112.4">BUF30</text>
<text x="274.5" y="112.4">BUF32</text>
<text x="278.6" y="112" transform="rotate(-90 278.6 112)">C80</text>
<text x="279.8" y="112" transform="rotate(-90 279.8 112)">1uf</text>
<text x="279.9" y="109.4">GND</text>
<text x="283.5" y="112.4">FILT32_OUT</text>
<text x="8.9" y="119.6">GND GND GND GND</text>
<text x="9.1" y="118.1" transform="rotate(-90 9.1 118.1)">R6</text>
<text x="9.5" y="114.8">PIN21PIN22PIN23PIN24</text>
<text x="10.2" y="118.1" transform="rotate(-90 10.2 118.1)">1M</text>
<text x="10.9" y="118.1" transform="rotate(-90 10.9 118.1)">R14</text>
<text x="12" y="118.1" transform="rotate(-90 12 118.1)">1M</text>
<text x="12.7" y="118.1" transform="rotate(-90 12.7 118.1)">R22</text>
<text x="13.8" y="118.1" transform="rotate(-90 13.8 118.1)">1M</text>
<text x="14.5" y="118.1" transform="rotate(-90 14.5 118.1)">R30</text>
<text x="15.6" y="118.1" transform="rotate(-90 15.6 118.1)">1M</text>
<text x="32.6" y="114.6">TP26</text>
<text x="32.6" y="115.8">TP27</text>
<text x="32.6" y="117">TP28</text>
<text x="32.6" y="118.2">TP29</text>
<text x="32.6" y="119.4">TP30</text>
<text x="36.5" y="114.8">PIN26</text>
<text x="36.5" y="116">PIN27</text>
<text x="36.5" y="117.2">PIN28</text>
<text x="36.5" y="118.4">PIN29</text>
<text x="36.5" y="119.6">PIN30</text>
<text x="56.2" y="114.8">PIN6</text>
<text x="56.2" y="116.6">PIN7</text>
<text x="56.2" y="118.4">PIN8</text>
<text x="68.2" y="114.8">BUF6</text>
<text x="68.2" y="116.6">BUF7</text>
<text x="68.2" y="118.4">BUF8</text>
<text x="108.4" y="114.8">BUF8</text>
<text x="112.5" y="114.4" transform="rotate(-90 112.5 114.4)">C26</text>
<text x="113.7" y="114.4" transform="rotate(-90 113.7 114.4)">1uf</text>
<text x="113.8" y="119.6">GND</text>
<text x="114" y="118.1" transform="rotate(-90 114 118.1)">R40</text>
<text x="115.2" y="118.1" transform="rotate(-90 115.2 118.1)">1.6M</text>
<text x="117.4" y="114.8">FILT8_OUT</text>
<text x="139.6" y="115.4">PIN19</text>
<text x="139.6" y="117.2">PIN20</text>
<text x="151.6" y="115.4">BUF19</text>
<text x="151.6" y="117.2">BUF20</text>
<text x="197.2" y="118.4">GND</text>
<text x="197.4" y="116.9" transform="rotate(-90 197.4 116.9)">R52</text>
<text x="198.5" y="116.9" transform="rotate(-90 198.5 116.9)">1.6M</text>
<text x="222.3" y="114.2">PIN31</text>
<text x="222.3" y="116">PIN32</text>
<text x="236.7" y="114.2">BUF31</text>
<text x="236.7" y="116">BUF32</text>
<text x="279.9" y="117.2">GND</text>
<text x="280.1" y="115.7" transform="rotate(-90 280.1 115.7)">R64</text>
<text x="281.3" y="115.7" transform="rotate(-90 281.3 115.7)">1.6M</text>
<text x="8.9" y="125.6">GND GND GND GND</text>
<text x="9.1" y="124.1" transform="rotate(-90 9.1 124.1)">R7</text>
<text x="9.5" y="120.8">PIN25PIN26PIN27PIN28</text>
<text x="10.2" y="124.1" transform="rotate(-90 10.2 124.1)">1M</text>
<text x="10.9" y="124.1" transform="rotate(-90 10.9 124.1)">R15</text>
<text x="12" y="124.1" transform="rotate(-90 12 124.1)">1M</text>
<text x="12.7" y="124.1" transform="rotate(-90 12.7 124.1)">R23</text>
<text x="13.8" y="124.1" transform="rotate(-90 13.8 124.1)">1M</text>
<text x="14.5" y="124.1" transform="rotate(-90 14.5 124.1)">R31</text>
<text x="15.6" y="124.1" transform="rotate(-90 15.6 124.1)">1M</text>
<text x="32.6" y="120.6">TP31</text>
<text x="32.6" y="121.8">TP32</text>
<text x="36.5" y="120.8">PIN31</text>
<text x="36.5" y="122">PIN32</text>
<text x="58" y="123.2">GND</text>
<text x="60.3" y="123.9" transform="rotate(-90 60.3 123.9)">0.1uF</text>
<text x="61.5" y="123.1" transform="rotate(-90 61.5 123.1)">C3</text>
<text x="62.2" y="125.6">V+</text>
<text x="62.8" y="122.6">V-</text>
<text x="81.4" y="125">V+</text>
<text x="83.7" y="125.8" transform="rotate(-90 83.7 125.8)">C17</text>
<text x="84.9" y="125.8" transform="rotate(-90 84.9 125.8)">0.1uF</text>
<text x="107.8" y="124.4">BUF9</text>
<text x="112.5" y="124.6" transform="rotate(-90 112.5 124.6)">C27</text>
<text x="113.7" y="124.6" transform="rotate(-90 113.7 124.6)">1uf</text>
<text x="116.8" y="125">FILT9_OUT</text>
<text x="141.4" y="122">GND</text>
<text x="143.7" y="122.7" transform="rotate(-90 143.7 122.7)">0.1uF</text>
<text x="144.9" y="122.3" transform="rotate(-90 144.9 122.3)">C33</text>
<text x="145.6" y="124.4">V+</text>
<text x="146.2" y="121.4">V-</text>
<text x="147.9" y="125.2" transform="rotate(-90 147.9 125.2)">C39</text>
<text x="149.1" y="125.2" transform="rotate(-90 149.1 125.2)">0.1uF</text>
<text x="164.8" y="123.8">V+</text>
<text x="167.1" y="124.6" transform="rotate(-90 167.1 124.6)">C47</text>
<text x="168.3" y="124.6" transform="rotate(-90 168.3 124.6)">0.1uF</text>
<text x="191.8" y="123.8">BUF21</text>
<text x="195.9" y="123.4" transform="rotate(-90 195.9 123.4)">C57</text>
<text x="197.1" y="123.4" transform="rotate(-90 197.1 123.4)">1uf</text>
<text x="200.2" y="123.8">FILT21_OUT</text>
<text x="224.1" y="120.8">GND</text>
<text x="226.4" y="121.5" transform="rotate(-90 226.4 121.5)">0.1uF</text>
<text x="227.6" y="121.1" transform="rotate(-90 227.6 121.1)">C62</text>
<text x="228.9" y="120.2">V-</text>
<text x="8.9" y="131.6">GND GND GND GND</text>
<text x="9.1" y="130.1" transform="rotate(-90 9.1 130.1)">R8</text>
<text x="9.5" y="126.8">PIN29PIN30PIN31PIN32</text>
<text x="10.2" y="130.1" transform="rotate(-90 10.2 130.1)">1M</text>
<text x="10.9" y="130.1" transform="rotate(-90 10.9 130.1)">R16</text>
<text x="12" y="130.1" transform="rotate(-90 12 130.1)">1M</text>
<text x="12.7" y="130.1" transform="rotate(-90 12.7 130.1)">R24</text>
<text x="13.8" y="130.1" transform="rotate(-90 13.8 130.1)">1M</text>
<text x="14.5" y="130.1" transform="rotate(-90 14.5 130.1)">R32</text>
<text x="15.6" y="130.1" transform="rotate(-90 15.6 130.1)">1M</text>
<text x="56.2" y="130.4">PIN9</text>
<text x="64.5" y="126.4" transform="rotate(-90 64.5 126.4)">C9</text>
<text x="65.7" y="126.4" transform="rotate(-90 65.7 126.4)">0.1uF</text>
<text x="66.4" y="128.6">GND</text>
<text x="68.8" y="130.4">BUF9</text>
<text x="74.2" y="129.8">FILT11_OUT</text>
<text x="74.2" y="131.6">FILT12_OUT</text>
<text x="85.6" y="128">GND</text>
<text x="89.2" y="129.8">FILT11_BUF</text>
<text x="89.8" y="131.6">FILT12_BUF</text>
<text x="113.8" y="129.8">GND</text>
<text x="114" y="128.3" transform="rotate(-90 114 128.3)">R41</text>
<text x="115.2" y="128.3" transform="rotate(-90 115.2 128.3)">1.6M</text>
<text x="138.4" y="129.2">PIN21</text>
<text x="138.4" y="131">PIN22</text>
<text x="149.8" y="127.4">GND</text>
<text x="152.2" y="129.2">BUF21</text>
<text x="152.2" y="131">BUF22</text>
<text x="157.6" y="128.6">FILT23_OUT</text>
<text x="157.6" y="130.4">FILT24_OUT</text>
<text x="169" y="126.8">GND</text>
<text x="172.6" y="128.6">FILT23_BUF</text>
<text x="172.6" y="130.4">FILT24_BUF</text>
<text x="191.8" y="131.6">BUF22</text>
<text x="195.9" y="131.2" transform="rotate(-90 195.9 131.2)">C58</text>
<text x="197.1" y="131.2" transform="rotate(-90 197.1 131.2)">1uf</text>
<text x="197.2" y="128.6">GND</text>
<text x="197.4" y="127.1" transform="rotate(-90 197.4 127.1)">R53</text>
<text x="198.5" y="127.1" transform="rotate(-90 198.5 127.1)">1.6M</text>
<text x="200.8" y="131.6">FILT22_OUT</text>
<text x="55" y="135.8">FILT9_OUT</text>
<text x="55" y="134">FILT10_OUT</text>
<text x="56.2" y="132.2">PIN10</text>
<text x="68.2" y="134">FILT10_BUF</text>
<text x="68.8" y="135.8">FILT9_BUF</text>
<text x="68.8" y="132.2">BUF10</text>
<text x="74.2" y="133.4">PIN11</text>
<text x="74.2" y="135.2">PIN12</text>
<text x="89.2" y="133.4">BUF11</text>
<text x="89.2" y="135.2">BUF12</text>
<text x="108.4" y="132.8">BUF10</text>
<text x="112.5" y="132.4" transform="rotate(-90 112.5 132.4)">C28</text>
<text x="113.7" y="132.4" transform="rotate(-90 113.7 132.4)">1uf</text>
<text x="113.8" y="137.6">GND</text>
<text x="114" y="136.1" transform="rotate(-90 114 136.1)">R42</text>
<text x="115.2" y="136.1" transform="rotate(-90 115.2 136.1)">1.6M</text>
<text x="117.4" y="132.8">FILT10_OUT</text>
<text x="138.4" y="134.6">FILT21_OUT</text>
<text x="138.4" y="132.8">FILT22_OUT</text>
<text x="152.2" y="134.6">FILT21_BUF</text>
<text x="152.2" y="132.8">FILT22_BUF</text>
<text x="157.6" y="132.2">PIN23</text>
<text x="157.6" y="134">PIN24</text>
<text x="172.6" y="132.2">BUF23</text>
<text x="172.6" y="134">BUF24</text>
<text x="197.2" y="136.4">GND</text>
<text x="197.4" y="134.9" transform="rotate(-90 197.4 134.9)">R54</text>
<text x="198.5" y="134.9" transform="rotate(-90 198.5 134.9)">1.6M</text>
<text x="57.4" y="141.2">GND</text>
<text x="59.7" y="141.3" transform="rotate(-90 59.7 141.3)">0.1uF</text>
<text x="60.9" y="140.5" transform="rotate(-90 60.9 140.5)">C2</text>
<text x="62.2" y="142.4">V+</text>
<text x="62.2" y="140">V-</text>
<text x="64.5" y="142.6" transform="rotate(-90 64.5 142.6)">C10</text>
<text x="65.7" y="142.6" transform="rotate(-90 65.7 142.6)">0.1uF</text>
<text x="76.6" y="140.6">GND</text>
<text x="78.9" y="140.7" transform="rotate(-90 78.9 140.7)">0.1uF</text>
<text x="80.1" y="140.2" transform="rotate(-90 80.1 140.2)">C14</text>
<text x="81.4" y="139.4">V-</text>
<text x="108.4" y="141.2">BUF11</text>
<text x="112.5" y="140.8" transform="rotate(-90 112.5 140.8)">C29</text>
<text x="113.7" y="140.8" transform="rotate(-90 113.7 140.8)">1uf</text>
<text x="117.4" y="141.2">FILT11_OUT</text>
<text x="140.8" y="140">GND</text>
<text x="143.1" y="140.1" transform="rotate(-90 143.1 140.1)">0.1uF</text>
<text x="144.3" y="139.6" transform="rotate(-90 144.3 139.6)">C32</text>
<text x="145.6" y="141.2">V+</text>
<text x="145.6" y="138.8">V-</text>
<text x="147.9" y="141.4" transform="rotate(-90 147.9 141.4)">C40</text>
<text x="149.1" y="141.4" transform="rotate(-90 149.1 141.4)">0.1uF</text>
<text x="149.8" y="143.6">GND</text>
<text x="160" y="139.4">GND</text>
<text x="162.3" y="139.5" transform="rotate(-90 162.3 139.5)">0.1uF</text>
<text x="163.5" y="139.1" transform="rotate(-90 163.5 139.1)">C44</text>
<text x="164.8" y="138.2">V-</text>
<text x="191.8" y="140">BUF23</text>
<text x="195.9" y="139.6" transform="rotate(-90 195.9 139.6)">C59</text>
<text x="197.1" y="139.6" transform="rotate(-90 197.1 139.6)">1uf</text>
<text x="197.4" y="143.3" transform="rotate(-90 197.4 143.3)">R55</text>
<text x="198.5" y="143.3" transform="rotate(-90 198.5 143.3)">1.6M</text>
<text x="200.8" y="140">FILT23_OUT</text>
<text x="55" y="148.4">PIN10</text>
<text x="55.6" y="146.6">PIN9</text>
<text x="66.4" y="144.8">GND</text>
<text x="69.4" y="146.6">BUF9</text>
<text x="69.4" y="148.4">BUF10</text>
<text x="108.4" y="149">BUF12</text>
<text x="112.5" y="148.6" transform="rotate(-90 112.5 148.6)">C30</text>
<text x="113.7" y="148.6" transform="rotate(-90 113.7 148.6)">1uf</text>
<text x="113.8" y="146">GND</text>
<text x="114" y="144.5" transform="rotate(-90 114 144.5)">R43</text>
<text x="115.2" y="144.5" transform="rotate(-90 115.2 144.5)">1.6M</text>
<text x="117.4" y="149">FILT12_OUT</text>
<text x="138.4" y="145.4">PIN21</text>
<text x="138.4" y="147.2">PIN22</text>
<text x="138.4" y="149">PIN23</text>
<text x="152.8" y="145.4">BUF21</text>
<text x="152.8" y="147.2">BUF22</text>
<text x="152.8" y="149">BUF23</text>
<text x="191.8" y="147.8">BUF24</text>
<text x="195.9" y="147.4" transform="rotate(-90 195.9 147.4)">C60</text>
<text x="197.1" y="147.4" transform="rotate(-90 197.1 147.4)">1uf</text>
<text x="197.2" y="144.8">GND</text>
<text x="200.8" y="147.8">FILT24_OUT</text>
<text x="55.6" y="150.2">PIN11</text>
<text x="56.2" y="152">PIN12</text>
<text x="69.4" y="150.2">BUF11</text>
<text x="69.4" y="152">BUF12</text>
<text x="113.8" y="153.8">GND</text>
<text x="114" y="152.3" transform="rotate(-90 114 152.3)">R44</text>
<text x="115.2" y="152.3" transform="rotate(-90 115.2 152.3)">1.6M</text>
<text x="138.4" y="150.8">PIN24</text>
<text x="141.4" y="155.6">GND</text>
<text x="144.9" y="155.8" transform="rotate(-90 144.9 155.8)">C34</text>
<text x="146.2" y="155">V-</text>
<text x="152.8" y="150.8">BUF24</text>
<text x="197.2" y="152.6">GND</text>
<text x="197.4" y="151.1" transform="rotate(-90 197.4 151.1)">R56</text>
<text x="198.5" y="151.1" transform="rotate(-90 198.5 151.1)">1.6M</text>
<text x="58" y="156.8">GND</text>
<text x="60.3" y="157.5" transform="rotate(-90 60.3 157.5)">0.1uF</text>
<text x="61.5" y="156.7" transform="rotate(-90 61.5 156.7)">C4</text>
<text x="62.8" y="156.2">V-</text>
<text x="143.7" y="156.3" transform="rotate(-90 143.7 156.3)">0.1uF</text>
</g>
<text font-size=".7" fill="#008000" x="32.3" y="61.4">TODO: Check if we want male or female D Sub</text>
<g font-size=".6" fill="#808080">
<text x="63.3" y="58.5" transform="rotate(-90 63.3 58.5)">3</text>
<text x="82.5" y="57.9" transform="rotate(-90 82.5 57.9)">3</text>
<text x="82.8" y="59.6" transform="rotate(-90 82.8 59.6)">V+</text>
<text x="143.6" y="59.6">1</text>
<text x="144.9" y="59.8">IN_A</text>
<text x="146.7" y="57.3" transform="rotate(-90 146.7 57.3)">3</text>
<text x="147" y="59" transform="rotate(-90 147 59)">V+</text>
<text x="147.5" y="59.8">OUT_A</text>
<text x="150.3" y="59.6">2</text>
<text x="162.7" y="59">1</text>
<text x="164.1" y="59.2">IN_A</text>
<text x="165.9" y="56.7" transform="rotate(-90 165.9 56.7)">3</text>
<text x="166.1" y="58.4" transform="rotate(-90 166.1 58.4)">V+</text>
<text x="166.7" y="59.2">OUT_A</text>
<text x="169.5" y="59">2</text>
<text x="226.3" y="58.4">1</text>
<text x="227.7" y="58.6">IN_A</text>
<text x="229.4" y="56.1" transform="rotate(-90 229.4 56.1)">3</text>
<text x="229.7" y="57.8" transform="rotate(-90 229.7 57.8)">V+</text>
<text x="230.2" y="58.6">OUT_A</text>
<text x="233.1" y="58.4">2</text>
<text x="245.5" y="57.8">1</text>
<text x="245.5" y="59.6">5</text>
<text x="246.9" y="58">IN_A</text>
<text x="246.9" y="59.8">IN_B</text>
<text x="248.6" y="55.5" transform="rotate(-90 248.6 55.5)">3</text>
<text x="248.9" y="57.2" transform="rotate(-90 248.9 57.2)">V+</text>
<text x="249.4" y="59.8">OUT_B</text>
<text x="249.4" y="58">OUT_A</text>
<text x="252.3" y="57.8">2</text>
<text x="252.3" y="59.6">4</text>
<text x="21.6" y="65.6">20</text>
<text x="24.4" y="65.6">1</text>
<text x="36.2" y="65.6">1</text>
<text x="38.8" y="65.6">20</text>
<text x="59.9" y="64.4">10</text>
<text x="60.2" y="60.8">1</text>
<text x="60.2" y="62.6">5</text>
<text x="61.6" y="61">IN_A</text>
<text x="61.6" y="62.8">IN_B</text>
<text x="61.6" y="64.6">IN_C</text>
<text x="63.6" y="60.2" transform="rotate(-90 63.6 60.2)">V+</text>
<text x="64.1" y="64.6">OUT_C</text>
<text x="64.1" y="62.8">OUT_B</text>
<text x="64.2" y="61">OUT_A</text>
<text x="67" y="60.8">2</text>
<text x="67" y="62.6">4</text>
<text x="67" y="64.4">9</text>
<text x="79.1" y="63.8">10</text>
<text x="79.4" y="60.2">1</text>
<text x="79.4" y="62">5</text>
<text x="79.4" y="65.6">6</text>
<text x="80.8" y="60.4">IN_A</text>
<text x="80.8" y="62.2">IN_B</text>
<text x="80.8" y="65.8">IN_D</text>
<text x="80.8" y="64">IN_C</text>
<text x="83.3" y="65.8">OUT_D</text>
<text x="83.3" y="64">OUT_C</text>
<text x="83.3" y="62.2">OUT_B</text>
<text x="83.3" y="60.4">OUT_A</text>
<text x="86.2" y="60.2">2</text>
<text x="86.2" y="62">4</text>
<text x="86.2" y="65.6">7</text>
<text x="86.2" y="63.8">9</text>
<text x="143.3" y="63.2">10</text>
<text x="143.6" y="61.4">5</text>
<text x="143.6" y="65">6</text>
<text x="144.9" y="61.6">IN_B</text>
<text x="144.9" y="65.2">IN_D</text>
<text x="144.9" y="63.4">IN_C</text>
<text x="147.5" y="65.2">OUT_D</text>
<text x="147.5" y="63.4">OUT_C</text>
<text x="147.5" y="61.6">OUT_B</text>
<text x="150.3" y="61.4">4</text>
<text x="150.3" y="65">7</text>
<text x="150.3" y="63.2">9</text>
<text x="162.5" y="62.6">10</text>
<text x="162.7" y="60.8">5</text>
<text x="162.7" y="64.4">6</text>
<text x="164.1" y="61">IN_B</text>
<text x="164.1" y="64.6">IN_D</text>
<text x="164.1" y="62.8">IN_C</text>
<text x="166.1" y="65.7" transform="rotate(-90 166.1 65.7)">V-</text>
<text x="166.6" y="64.6">OUT_D</text>
<text x="166.6" y="62.8">OUT_C</text>
<text x="166.7" y="61">OUT_B</text>
<text x="169.5" y="60.8">4</text>
<text x="169.5" y="64.4">7</text>
<text x="169.5" y="62.6">9</text>
<text x="226" y="62">10</text>
<text x="226.3" y="60.2">5</text>
<text x="226.3" y="63.8">6</text>
<text x="227.7" y="60.4">IN_B</text>
<text x="227.7" y="64">IN_D</text>
<text x="227.7" y="62.2">IN_C</text>
<text x="229.7" y="65.1" transform="rotate(-90 229.7 65.1)">V-</text>
<text x="230.2" y="64">OUT_D</text>
<text x="230.2" y="62.2">OUT_C</text>
<text x="230.2" y="60.4">OUT_B</text>
<text x="233.1" y="60.2">4</text>
<text x="233.1" y="63.8">7</text>
<text x="233.1" y="62">9</text>
<text x="245.2" y="61.4">10</text>
<text x="245.5" y="63.2">6</text>
<text x="246.9" y="63.4">IN_D</text>
<text x="246.9" y="61.6">IN_C</text>
<text x="248.6" y="65.9" transform="rotate(-90 248.6 65.9)">8</text>
<text x="248.9" y="64.5" transform="rotate(-90 248.9 64.5)">V-</text>
<text x="249.4" y="63.4">OUT_D</text>
<text x="249.4" y="61.6">OUT_C</text>
<text x="252.3" y="63.2">7</text>
<text x="252.3" y="61.4">9</text>
<text x="21.6" y="66.2">21</text>
<text x="21.6" y="66.8">22</text>
<text x="21.6" y="67.4">23</text>
<text x="21.6" y="68">24</text>
<text x="21.6" y="68.6">25</text>
<text x="21.6" y="69.2">26</text>
<text x="21.6" y="69.8">27</text>
<text x="21.6" y="70.4">28</text>
<text x="21.6" y="71">29</text>
<text x="21.6" y="71.6">30</text>
<text x="24.4" y="66.2">2</text>
<text x="24.4" y="66.8">3</text>
<text x="24.4" y="67.4">4</text>
<text x="24.4" y="68">5</text>
<text x="24.4" y="68.6">6</text>
<text x="24.4" y="69.2">7</text>
<text x="24.4" y="69.8">8</text>
<text x="24.4" y="70.4">9</text>
<text x="24.4" y="71">10</text>
<text x="24.4" y="71.6">11</text>
<text x="35.9" y="71">10</text>
<text x="36" y="71.6">11</text>
<text x="36.2" y="66.2">2</text>
<text x="36.2" y="66.8">3</text>
<text x="36.2" y="67.4">4</text>
<text x="36.2" y="68">5</text>
<text x="36.2" y="68.6">6</text>
<text x="36.2" y="69.2">7</text>
<text x="36.2" y="69.8">8</text>
<text x="36.2" y="70.4">9</text>
<text x="38.8" y="66.2">21</text>
<text x="38.8" y="66.8">22</text>
<text x="38.8" y="67.4">23</text>
<text x="38.8" y="68">24</text>
<text x="38.8" y="68.6">25</text>
<text x="38.8" y="69.2">26</text>
<text x="38.8" y="69.8">27</text>
<text x="38.8" y="70.4">28</text>
<text x="38.8" y="71">29</text>
<text x="38.8" y="71.6">30</text>
<text x="60.2" y="66.2">6</text>
<text x="61.6" y="66.4">IN_D</text>
<text x="63.3" y="68.9" transform="rotate(-90 63.3 68.9)">8</text>
<text x="63.6" y="67.5" transform="rotate(-90 63.6 67.5)">V-</text>
<text x="64.1" y="66.4">OUT_D</text>
<text x="67" y="66.2">7</text>
<text x="82.5" y="68.3" transform="rotate(-90 82.5 68.3)">8</text>
<text x="82.8" y="66.9" transform="rotate(-90 82.8 66.9)">V-</text>
<text x="146.7" y="67.7" transform="rotate(-90 146.7 67.7)">8</text>
<text x="147" y="66.3" transform="rotate(-90 147 66.3)">V-</text>
<text x="165.9" y="67.1" transform="rotate(-90 165.9 67.1)">8</text>
<text x="229.4" y="66.5" transform="rotate(-90 229.4 66.5)">8</text>
<text x="21.6" y="72.2">31</text>
<text x="21.6" y="72.7">32</text>
<text x="21.6" y="73.3">33</text>
<text x="21.6" y="73.9">34</text>
<text x="21.6" y="74.5">35</text>
<text x="21.6" y="75.1">36</text>
<text x="21.6" y="75.7">37</text>
<text x="24.4" y="72.2">12</text>
<text x="24.4" y="72.7">13</text>
<text x="24.4" y="73.3">14</text>
<text x="24.4" y="73.9">15</text>
<text x="24.4" y="74.5">16</text>
<text x="24.4" y="75.1">17</text>
<text x="24.4" y="75.7">18</text>
<text x="24.4" y="76.3">19</text>
<text x="35.9" y="72.2">12</text>
<text x="35.9" y="72.7">13</text>
<text x="35.9" y="73.3">14</text>
<text x="35.9" y="73.9">15</text>
<text x="35.9" y="74.5">16</text>
<text x="35.9" y="75.1">17</text>
<text x="35.9" y="75.7">18</text>
<text x="35.9" y="76.3">19</text>
<text x="38.8" y="72.2">31</text>
<text x="38.8" y="72.7">32</text>
<text x="38.8" y="73.3">33</text>
<text x="38.8" y="73.9">34</text>
<text x="38.8" y="74.5">35</text>
<text x="38.8" y="75.1">36</text>
<text x="38.8" y="75.7">37</text>
<text x="60.2" y="76.9">1</text>
<text x="61.6" y="77.2">IN_A</text>
<text x="63.3" y="74.7" transform="rotate(-90 63.3 74.7)">3</text>
<text x="63.6" y="76.4" transform="rotate(-90 63.6 76.4)">V+</text>
<text x="64.2" y="77.2">OUT_A</text>
<text x="67" y="76.9">2</text>
<text x="143.6" y="75.7">1</text>
<text x="143.6" y="77.5">5</text>
<text x="144.9" y="76">IN_A</text>
<text x="144.9" y="77.8">IN_B</text>
<text x="146.7" y="73.5" transform="rotate(-90 146.7 73.5)">3</text>
<text x="147" y="75.2" transform="rotate(-90 147 75.2)">V+</text>
<text x="147.5" y="77.8">OUT_B</text>
<text x="147.5" y="76">OUT_A</text>
<text x="150.3" y="75.7">2</text>
<text x="150.3" y="77.5">4</text>
<text x="226.3" y="74.5">1</text>
<text x="226.3" y="76.3">5</text>
<text x="227.7" y="74.8">IN_A</text>
<text x="227.7" y="76.6">IN_B</text>
<text x="229.4" y="72.3" transform="rotate(-90 229.4 72.3)">3</text>
<text x="229.7" y="74" transform="rotate(-90 229.7 74)">V+</text>
<text x="230.2" y="76.6">OUT_B</text>
<text x="230.2" y="74.8">OUT_A</text>
<text x="233.1" y="74.5">2</text>
<text x="233.1" y="76.3">4</text>
<text x="59.9" y="80.5">10</text>
<text x="60.2" y="78.7">5</text>
<text x="60.2" y="82.3">6</text>
<text x="61.6" y="79">IN_B</text>
<text x="61.6" y="82.6">IN_D</text>
<text x="61.6" y="80.8">IN_C</text>
<text x="63.6" y="83.7" transform="rotate(-90 63.6 83.7)">V-</text>
<text x="64.1" y="82.6">OUT_D</text>
<text x="64.1" y="80.8">OUT_C</text>
<text x="64.1" y="79">OUT_B</text>
<text x="67" y="78.7">4</text>
<text x="67" y="82.3">7</text>
<text x="67" y="80.5">9</text>
<text x="143.3" y="79.3">10</text>
<text x="143.6" y="81.1">6</text>
<text x="144.9" y="81.4">IN_D</text>
<text x="144.9" y="79.6">IN_C</text>
<text x="146.7" y="83.9" transform="rotate(-90 146.7 83.9)">8</text>
<text x="147" y="82.5" transform="rotate(-90 147 82.5)">V-</text>
<text x="147.5" y="81.4">OUT_D</text>
<text x="147.5" y="79.6">OUT_C</text>
<text x="150.3" y="81.1">7</text>
<text x="150.3" y="79.3">9</text>
<text x="226" y="78.1">10</text>
<text x="226.3" y="79.9">6</text>
<text x="227.7" y="80.2">IN_D</text>
<text x="227.7" y="78.4">IN_C</text>
<text x="229.4" y="82.7" transform="rotate(-90 229.4 82.7)">8</text>
<text x="229.7" y="81.3" transform="rotate(-90 229.7 81.3)">V-</text>
<text x="230.2" y="80.2">OUT_D</text>
<text x="230.2" y="78.4">OUT_C</text>
<text x="233.1" y="79.9">7</text>
<text x="233.1" y="78.1">9</text>
<text x="63.3" y="85.1" transform="rotate(-90 63.3 85.1)">8</text>
<text x="62.1" y="94.5" transform="rotate(-90 62.1 94.5)">3</text>
<text x="81.3" y="93.9" transform="rotate(-90 81.3 93.9)">3</text>
<text x="81.6" y="95.6" transform="rotate(-90 81.6 95.6)">V+</text>
<text x="142.4" y="95.5">1</text>
<text x="143.7" y="95.8">IN_A</text>
<text x="145.5" y="93.3" transform="rotate(-90 145.5 93.3)">3</text>
<text x="145.8" y="95" transform="rotate(-90 145.8 95)">V+</text>
<text x="146.3" y="95.8">OUT_A</text>
<text x="149.1" y="95.5">2</text>
<text x="161.5" y="94.9">1</text>
<text x="162.9" y="95.2">IN_A</text>
<text x="164.7" y="92.7" transform="rotate(-90 164.7 92.7)">3</text>
<text x="164.9" y="94.4" transform="rotate(-90 164.9 94.4)">V+</text>
<text x="165.5" y="95.2">OUT_A</text>
<text x="168.3" y="94.9">2</text>
<text x="225.1" y="94.3">1</text>
<text x="226.5" y="94.6">IN_A</text>
<text x="228.2" y="92.1" transform="rotate(-90 228.2 92.1)">3</text>
<text x="228.5" y="93.8" transform="rotate(-90 228.5 93.8)">V+</text>
<text x="229" y="94.6">OUT_A</text>
<text x="231.9" y="94.3">2</text>
<text x="244.3" y="93.7">1</text>
<text x="244.3" y="95.5">5</text>
<text x="245.7" y="94">IN_A</text>
<text x="245.7" y="95.8">IN_B</text>
<text x="247.4" y="91.5" transform="rotate(-90 247.4 91.5)">3</text>
<text x="247.7" y="93.2" transform="rotate(-90 247.7 93.2)">V+</text>
<text x="248.2" y="95.8">OUT_B</text>
<text x="248.2" y="94">OUT_A</text>
<text x="251.1" y="93.7">2</text>
<text x="251.1" y="95.5">4</text>
<text x="58.7" y="100.3">10</text>
<text x="59" y="96.7">1</text>
<text x="59" y="98.5">5</text>
<text x="60.4" y="97">IN_A</text>
<text x="60.4" y="98.8">IN_B</text>
<text x="60.4" y="100.6">IN_C</text>
<text x="62.4" y="96.2" transform="rotate(-90 62.4 96.2)">V+</text>
<text x="62.9" y="100.6">OUT_C</text>
<text x="62.9" y="98.8">OUT_B</text>
<text x="63" y="97">OUT_A</text>
<text x="65.8" y="96.7">2</text>
<text x="65.8" y="98.5">4</text>
<text x="65.8" y="100.3">9</text>
<text x="77.9" y="99.7">10</text>
<text x="78.2" y="96.1">1</text>
<text x="78.2" y="97.9">5</text>
<text x="78.2" y="101.5">6</text>
<text x="79.6" y="96.4">IN_A</text>
<text x="79.6" y="98.2">IN_B</text>
<text x="79.6" y="101.8">IN_D</text>
<text x="79.6" y="100">IN_C</text>
<text x="82.1" y="101.8">OUT_D</text>
<text x="82.1" y="100">OUT_C</text>
<text x="82.1" y="98.2">OUT_B</text>
<text x="82.1" y="96.4">OUT_A</text>
<text x="85" y="96.1">2</text>
<text x="85" y="97.9">4</text>
<text x="85" y="101.5">7</text>
<text x="85" y="99.7">9</text>
<text x="142.1" y="99.1">10</text>
<text x="142.4" y="97.3">5</text>
<text x="142.4" y="100.9">6</text>
<text x="143.7" y="97.6">IN_B</text>
<text x="143.7" y="101.2">IN_D</text>
<text x="143.7" y="99.4">IN_C</text>
<text x="146.3" y="101.2">OUT_D</text>
<text x="146.3" y="99.4">OUT_C</text>
<text x="146.3" y="97.6">OUT_B</text>
<text x="149.1" y="97.3">4</text>
<text x="149.1" y="100.9">7</text>
<text x="149.1" y="99.1">9</text>
<text x="161.3" y="98.5">10</text>
<text x="161.5" y="96.7">5</text>
<text x="161.5" y="100.3">6</text>
<text x="162.9" y="97">IN_B</text>
<text x="162.9" y="100.6">IN_D</text>
<text x="162.9" y="98.8">IN_C</text>
<text x="164.9" y="101.6" transform="rotate(-90 164.9 101.6)">V-</text>
<text x="165.4" y="100.6">OUT_D</text>
<text x="165.4" y="98.8">OUT_C</text>
<text x="165.5" y="97">OUT_B</text>
<text x="168.3" y="96.7">4</text>
<text x="168.3" y="100.3">7</text>
<text x="168.3" y="98.5">9</text>
<text x="224.8" y="97.9">10</text>
<text x="225.1" y="96.1">5</text>
<text x="225.1" y="99.7">6</text>
<text x="226.5" y="96.4">IN_B</text>
<text x="226.5" y="100">IN_D</text>
<text x="226.5" y="98.2">IN_C</text>
<text x="228.5" y="101" transform="rotate(-90 228.5 101)">V-</text>
<text x="229" y="100">OUT_D</text>
<text x="229" y="98.2">OUT_C</text>
<text x="229" y="96.4">OUT_B</text>
<text x="231.9" y="96.1">4</text>
<text x="231.9" y="99.7">7</text>
<text x="231.9" y="97.9">9</text>
<text x="244" y="97.3">10</text>
<text x="244.3" y="99.1">6</text>
<text x="245.7" y="99.4">IN_D</text>
<text x="245.7" y="97.6">IN_C</text>
<text x="247.4" y="101.8" transform="rotate(-90 247.4 101.8)">8</text>
<text x="247.7" y="100.4" transform="rotate(-90 247.7 100.4)">V-</text>
<text x="248.2" y="99.4">OUT_D</text>
<text x="248.2" y="97.6">OUT_C</text>
<text x="251.1" y="99.1">7</text>
<text x="251.1" y="97.3">9</text>
<text x="59" y="102.1">6</text>
<text x="60.4" y="102.4">IN_D</text>
<text x="62.1" y="104.8" transform="rotate(-90 62.1 104.8)">8</text>
<text x="62.4" y="103.4" transform="rotate(-90 62.4 103.4)">V-</text>
<text x="62.9" y="102.4">OUT_D</text>
<text x="65.8" y="102.1">7</text>
<text x="81.3" y="104.2" transform="rotate(-90 81.3 104.2)">8</text>
<text x="81.6" y="102.8" transform="rotate(-90 81.6 102.8)">V-</text>
<text x="145.5" y="103.6" transform="rotate(-90 145.5 103.6)">8</text>
<text x="145.8" y="102.2" transform="rotate(-90 145.8 102.2)">V-</text>
<text x="164.7" y="103" transform="rotate(-90 164.7 103)">8</text>
<text x="228.2" y="102.4" transform="rotate(-90 228.2 102.4)">8</text>
<text x="59" y="112.9">1</text>
<text x="60.4" y="113.2">IN_A</text>
<text x="62.1" y="110.6" transform="rotate(-90 62.1 110.6)">3</text>
<text x="62.4" y="112.4" transform="rotate(-90 62.4 112.4)">V+</text>
<text x="63" y="113.2">OUT_A</text>
<text x="65.8" y="112.9">2</text>
<text x="142.4" y="111.7">1</text>
<text x="142.4" y="113.5">5</text>
<text x="143.7" y="112">IN_A</text>
<text x="143.7" y="113.8">IN_B</text>
<text x="145.5" y="109.5" transform="rotate(-90 145.5 109.5)">3</text>
<text x="145.8" y="111.2" transform="rotate(-90 145.8 111.2)">V+</text>
<text x="146.3" y="113.8">OUT_B</text>
<text x="146.3" y="112">OUT_A</text>
<text x="149.1" y="111.7">2</text>
<text x="149.1" y="113.5">4</text>
<text x="225.1" y="110.5">1</text>
<text x="225.1" y="112.3">5</text>
<text x="226.5" y="110.8">IN_A</text>
<text x="226.5" y="112.6">IN_B</text>
<text x="228.2" y="108.3" transform="rotate(-90 228.2 108.3)">3</text>
<text x="228.5" y="110" transform="rotate(-90 228.5 110)">V+</text>
<text x="229" y="112.6">OUT_B</text>
<text x="229" y="110.8">OUT_A</text>
<text x="231.9" y="110.5">2</text>
<text x="231.9" y="112.3">4</text>
<text x="58.7" y="116.5">10</text>
<text x="59" y="114.7">5</text>
<text x="59" y="118.3">6</text>
<text x="60.4" y="115">IN_B</text>
<text x="60.4" y="118.6">IN_D</text>
<text x="60.4" y="116.8">IN_C</text>
<text x="62.4" y="119.6" transform="rotate(-90 62.4 119.6)">V-</text>
<text x="62.9" y="118.6">OUT_D</text>
<text x="62.9" y="116.8">OUT_C</text>
<text x="62.9" y="115">OUT_B</text>
<text x="65.8" y="114.7">4</text>
<text x="65.8" y="118.3">7</text>
<text x="65.8" y="116.5">9</text>
<text x="142.1" y="115.3">10</text>
<text x="142.4" y="117.1">6</text>
<text x="143.7" y="117.4">IN_D</text>
<text x="143.7" y="115.6">IN_C</text>
<text x="145.5" y="119.8" transform="rotate(-90 145.5 119.8)">8</text>
<text x="145.8" y="118.4" transform="rotate(-90 145.8 118.4)">V-</text>
<text x="146.3" y="117.4">OUT_D</text>
<text x="146.3" y="115.6">OUT_C</text>
<text x="149.1" y="117.1">7</text>
<text x="149.1" y="115.3">9</text>
<text x="224.8" y="114.1">10</text>
<text x="225.1" y="115.9">6</text>
<text x="226.5" y="116.2">IN_D</text>
<text x="226.5" y="114.4">IN_C</text>
<text x="228.2" y="118.6" transform="rotate(-90 228.2 118.6)">8</text>
<text x="228.5" y="117.2" transform="rotate(-90 228.5 117.2)">V-</text>
<text x="229" y="116.2">OUT_D</text>
<text x="229" y="114.4">OUT_C</text>
<text x="231.9" y="115.9">7</text>
<text x="231.9" y="114.1">9</text>
<text x="62.1" y="121" transform="rotate(-90 62.1 121)">8</text>
<text x="59" y="130.3">1</text>
<text x="60.4" y="130.6">IN_A</text>
<text x="62.1" y="128" transform="rotate(-90 62.1 128)">3</text>
<text x="62.4" y="129.8" transform="rotate(-90 62.4 129.8)">V+</text>
<text x="63" y="130.6">OUT_A</text>
<text x="65.8" y="130.3">2</text>
<text x="78.2" y="129.7">1</text>
<text x="78.2" y="131.5">5</text>
<text x="79.6" y="130">IN_A</text>
<text x="79.6" y="131.8">IN_B</text>
<text x="81.3" y="127.4" transform="rotate(-90 81.3 127.4)">3</text>
<text x="81.6" y="129.2" transform="rotate(-90 81.6 129.2)">V+</text>
<text x="82.1" y="131.8">OUT_B</text>
<text x="82.1" y="130">OUT_A</text>
<text x="85" y="129.7">2</text>
<text x="85" y="131.5">4</text>
<text x="142.4" y="129.1">1</text>
<text x="142.4" y="130.9">5</text>
<text x="143.7" y="129.4">IN_A</text>
<text x="143.7" y="131.2">IN_B</text>
<text x="145.5" y="126.8" transform="rotate(-90 145.5 126.8)">3</text>
<text x="145.8" y="128.6" transform="rotate(-90 145.8 128.6)">V+</text>
<text x="146.3" y="131.2">OUT_B</text>
<text x="146.3" y="129.4">OUT_A</text>
<text x="149.1" y="129.1">2</text>
<text x="149.1" y="130.9">4</text>
<text x="161.5" y="128.5">1</text>
<text x="161.5" y="130.3">5</text>
<text x="162.9" y="128.8">IN_A</text>
<text x="162.9" y="130.6">IN_B</text>
<text x="164.7" y="126.2" transform="rotate(-90 164.7 126.2)">3</text>
<text x="164.9" y="128" transform="rotate(-90 164.9 128)">V+</text>
<text x="165.5" y="130.6">OUT_B</text>
<text x="165.5" y="128.8">OUT_A</text>
<text x="168.3" y="128.5">2</text>
<text x="168.3" y="130.3">4</text>
<text x="58.7" y="133.9">10</text>
<text x="59" y="132.1">5</text>
<text x="59" y="135.7">6</text>
<text x="60.4" y="132.4">IN_B</text>
<text x="60.4" y="136">IN_D</text>
<text x="60.4" y="134.2">IN_C</text>
<text x="62.4" y="137" transform="rotate(-90 62.4 137)">V-</text>
<text x="62.9" y="136">OUT_D</text>
<text x="62.9" y="134.2">OUT_C</text>
<text x="62.9" y="132.4">OUT_B</text>
<text x="65.8" y="132.1">4</text>
<text x="65.8" y="135.7">7</text>
<text x="65.8" y="133.9">9</text>
<text x="77.9" y="133.3">10</text>
<text x="78.2" y="135.1">6</text>
<text x="79.6" y="135.4">IN_D</text>
<text x="79.6" y="133.6">IN_C</text>
<text x="81.3" y="137.8" transform="rotate(-90 81.3 137.8)">8</text>
<text x="81.6" y="136.4" transform="rotate(-90 81.6 136.4)">V-</text>
<text x="82.1" y="135.4">OUT_D</text>
<text x="82.1" y="133.6">OUT_C</text>
<text x="85" y="135.1">7</text>
<text x="85" y="133.3">9</text>
<text x="142.1" y="132.7">10</text>
<text x="142.4" y="134.5">6</text>
<text x="143.7" y="134.8">IN_D</text>
<text x="143.7" y="133">IN_C</text>
<text x="145.5" y="137.2" transform="rotate(-90 145.5 137.2)">8</text>
<text x="145.8" y="135.8" transform="rotate(-90 145.8 135.8)">V-</text>
<text x="146.3" y="134.8">OUT_D</text>
<text x="146.3" y="133">OUT_C</text>
<text x="149.1" y="134.5">7</text>
<text x="149.1" y="132.7">9</text>
<text x="161.3" y="132.1">10</text>
<text x="161.5" y="133.9">6</text>
<text x="162.9" y="134.2">IN_D</text>
<text x="162.9" y="132.4">IN_C</text>
<text x="164.7" y="136.6" transform="rotate(-90 164.7 136.6)">8</text>
<text x="164.9" y="135.2" transform="rotate(-90 164.9 135.2)">V-</text>
<text x="165.4" y="134.2">OUT_D</text>
<text x="165.4" y="132.4">OUT_C</text>
<text x="168.3" y="133.9">7</text>
<text x="168.3" y="132.1">9</text>
<text x="62.1" y="138.4" transform="rotate(-90 62.1 138.4)">8</text>
<text x="145.5" y="143" transform="rotate(-90 145.5 143)">3</text>
<text x="59" y="146.5">1</text>
<text x="59" y="148.3">5</text>
<text x="60.4" y="146.8">IN_A</text>
<text x="60.4" y="148.5">IN_B</text>
<text x="62.1" y="144.2" transform="rotate(-90 62.1 144.2)">3</text>
<text x="62.4" y="146" transform="rotate(-90 62.4 146)">V+</text>
<text x="62.9" y="148.5">OUT_B</text>
<text x="63" y="146.8">OUT_A</text>
<text x="65.8" y="146.5">2</text>
<text x="65.8" y="148.3">4</text>
<text x="142.1" y="148.9">10</text>
<text x="142.4" y="145.3">1</text>
<text x="142.4" y="147.1">5</text>
<text x="143.7" y="145.6">IN_A</text>
<text x="143.7" y="147.4">IN_B</text>
<text x="143.7" y="149.1">IN_C</text>
<text x="145.8" y="144.8" transform="rotate(-90 145.8 144.8)">V+</text>
<text x="146.3" y="149.1">OUT_C</text>
<text x="146.3" y="147.4">OUT_B</text>
<text x="146.3" y="145.6">OUT_A</text>
<text x="149.1" y="145.3">2</text>
<text x="149.1" y="147.1">4</text>
<text x="149.1" y="148.9">9</text>
<text x="58.7" y="150.1">10</text>
<text x="59" y="151.9">6</text>
<text x="60.4" y="152.1">IN_D</text>
<text x="60.4" y="150.3">IN_C</text>
<text x="62.1" y="154.6" transform="rotate(-90 62.1 154.6)">8</text>
<text x="62.4" y="153.2" transform="rotate(-90 62.4 153.2)">V-</text>
<text x="62.9" y="152.1">OUT_D</text>
<text x="62.9" y="150.3">OUT_C</text>
<text x="65.8" y="151.9">7</text>
<text x="65.8" y="150.1">9</text>
<text x="142.4" y="150.7">6</text>
<text x="143.7" y="150.9">IN_D</text>
<text x="145.5" y="153.4" transform="rotate(-90 145.5 153.4)">8</text>
<text x="145.8" y="152" transform="rotate(-90 145.8 152)">V-</text>
<text x="146.3" y="150.9">OUT_D</text>
<text x="149.1" y="150.7">7</text>
</g>
<g font-size=".5" fill="#800000">
<text x="59.8" y="58.4">Voltage Buffers</text>
<text x="79" y="57.8">Voltage Buffers</text>
<text x="143.2" y="57.2">Voltage Buffers</text>
<text x="162.4" y="56.6">Voltage Buffers</text>
<text x="225.9" y="56">Voltage Buffers</text>
<text x="245.1" y="55.4">Voltage Buffers</text>
<text x="59.8" y="74.6">Voltage Buffers</text>
<text x="143.2" y="73.4">Voltage Buffers</text>
<text x="225.9" y="72.2">Voltage Buffers</text>
<text x="58.6" y="94.4">Voltage Buffers</text>
<text x="77.8" y="93.8">Voltage Buffers</text>
<text x="142" y="93.2">Voltage Buffers</text>
<text x="161.2" y="92.6">Voltage Buffers</text>
<text x="224.7" y="92">Voltage Buffers</text>
<text x="243.9" y="91.4">Voltage Buffers</text>
<text x="58.6" y="110.6">Voltage Buffers</text>
<text x="142" y="109.4">Voltage Buffers</text>
<text x="224.7" y="108.2">Voltage Buffers</text>
<text x="58.6" y="128">Voltage Buffers</text>
<text x="77.8" y="127.4">Voltage Buffers</text>
<text x="142" y="126.8">Voltage Buffers</text>
<text x="161.2" y="126.2">Voltage Buffers</text>
<text x="142" y="143">Voltage Buffers</text>
<text x="58.6" y="144.2">Voltage Buffers</text>
</g>
</g></defs>
<g fill="none" stroke="#800000" stroke-width=".13">
<path d="M61 59.1h5.4v8.9h-5.4zM63.4 57.8v1.3M65.2 57.3h.8M66.3 57.3h.7M67.8 58.4h.9M68.2 57.8v.6M80.2 58.4h5.4v9h-5.4zM82.6 57.3v1.1M82.6 59.6l.6 .6-.6 .7zM84.4 56.6h.7M85.5 56.6h.7M87 57.8h.9"/>
<path d="M87.4 57.3v.5M112 57.3h.7M113.1 57.3h.7M114.2 59.1h.4v1.1h-.4zM114.4 58.4v.7M143.2 59.6h3.6M144.4 57.8h5.4v9h-5.4zM146.8 56.6v1.2M146.8 59.1l.6 .5-.6 .6zM147.4 59.6h3.6M148.6 56h.7M149.6 56h.8"/>
<path d="M151.1 57.3h.9M151.6 56.6v.7M162.4 59.1h3.6M163.6 57.3h5.4v8.9h-5.4zM166 56v1.3M166 58.4l.6 .7-.6 .5zM166.6 59.1h3.6M167.8 55.5h.7M168.8 55.5h.8M170.3 56.6h.9M170.8 56v.6M195.3 56h.8"/>
<path d="M196.4 56h.7M197.5 57.8h.5v1.3h-.5zM197.7 57.3v.5M197.7 59.1v1.1M225.9 58.4h3.6M227.1 56.6h5.4v9h-5.4zM229.5 55.5v1.1M229.5 57.8l.6 .6-.6 .7zM229.5 59.6l.6 .6-.6 .7zM230.1 58.4h3.6M231.3 54.8h.8M232.4 54.8h.7"/>
<path d="M233.9 56h.9M234.3 55.5v.5M245.1 57.8h3.6M245.1 59.6h3.6M246.3 56h5.4v9h-5.4zM248.7 54.8v1.2M248.7 57.3l.6 .5-.6 .6zM248.7 59.1l.6 .5-.6 .6zM249.3 57.8h3.6M249.3 59.6h3.6M250.5 54.3h.7M251.6 54.3h.7"/>
<path d="M253.1 55.5h.9M253.5 54.8v.7M278.1 54.8h.7M279.2 54.8h.7M280 59.1h.9M280.3 56.6h.4v1.2h-.4zM280.5 56v.6M280.5 57.8v1.3M21.5 66.2h1.1M21.5 68h1.1M21.5 75.2h1.1M21.5 65.6h1.1"/>
<path d="M21.5 66.8h1.1M21.5 67.4h1.1M21.5 68.6h1.1M21.5 69.2h1.1M21.5 69.8h1.1M21.5 70.4h1.1M21.5 71h1.1M21.5 71.6h1.1M21.5 72.2h1.1M21.5 72.8h1.1M21.5 73.4h1.1M21.5 74h1.1"/>
<path d="M21.5 74.6h1.1M21.5 75.8h1.1M22.4 65.3l1.5-.4a.27 .27 0 0 1 .3 .3v11.7a.27 .27 0 0 1-.3 .3l-1.4-.3-.2-.3v-11.1zM23.9 66.2h1.2M23.9 68h1.2M23.9 75.2h1.2M23.9 65.6h1.2M23.9 66.8h1.2M23.9 67.4h1.2M23.9 68.6h1.2M23.9 69.2h1.2M23.9 69.8h1.2"/>
<path d="M23.9 70.4h1.2M23.9 71h1.2M23.9 71.6h1.2M23.9 72.2h1.2M23.9 72.8h1.2M23.9 73.4h1.2M23.9 74h1.2M23.9 74.6h1.2M23.9 75.8h1.2M23.9 76.4h1.2M35.9 66.2h1.1M35.9 68h1.1"/>
<path d="M35.9 75.2h1.1M35.9 65.6h1.1M35.9 66.8h1.1M35.9 67.4h1.1M35.9 68.6h1.1M35.9 69.2h1.1M35.9 69.8h1.1M35.9 70.4h1.1M35.9 71h1.1M35.9 71.6h1.1M35.9 72.2h1.1M35.9 72.8h1.1"/>
<path d="M35.9 73.4h1.1M35.9 74h1.1M35.9 74.6h1.1M35.9 75.8h1.1M35.9 76.4h1.1M36.8 65l.3-.1 1.3 .3 .2 .3v11.1l-.2 .3-1.3 .3a.3 .3 0 0 1-.4-.3v-11.7zM37.3 65.4a.21 .21 0 0 0-.3 .2 .21 .21 0 0 0 .3 .2M37.3 66a.2 .2 0 0 0-.3 .2 .2 .2 0 0 0 .3 .2M37.3 66.6a.21 .21 0 0 0-.3 .2 .21 .21 0 0 0 .3 .3M37.3 67.2a.21 .21 0 0 0-.3 .2 .21 .21 0 0 0 .3 .2M37.3 67.8a.21 .21 0 0 0-.3 .2 .21 .21 0 0 0 .3 .2M37.3 68.4a.21 .21 0 0 0-.3 .2 .21 .21 0 0 0 .3 .3"/>
<path d="M37.3 69a.21 .21 0 0 0-.3 .2 .21 .21 0 0 0 .3 .2M37.3 69.6a.21 .21 0 0 0-.3 .2 .21 .21 0 0 0 .3 .2M37.3 70.2a.21 .21 0 0 0-.3 .2 .21 .21 0 0 0 .3 .3M37.3 70.8a.21 .21 0 0 0-.3 .2 .21 .21 0 0 0 .3 .2M37.3 71.4a.21 .21 0 0 0-.3 .2 .21 .21 0 0 0 .3 .2M37.3 72a.21 .21 0 0 0-.3 .2 .21 .21 0 0 0 .3 .3M37.3 72.6a.21 .21 0 0 0-.3 .2 .21 .21 0 0 0 .3 .2M37.3 73.2a.21 .21 0 0 0-.3 .2 .21 .21 0 0 0 .3 .2M37.3 73.8a.21 .21 0 0 0-.3 .2 .21 .21 0 0 0 .3 .3M37.3 74.4a.21 .21 0 0 0-.3 .2 .21 .21 0 0 0 .3 .2M37.3 75a.21 .21 0 0 0-.3 .2 .21 .21 0 0 0 .3 .2M37.3 75.6a.2 .2 0 0 0-.3 .2 .2 .2 0 0 0 .3 .2"/>
<path d="M37.3 76.2a.21 .21 0 0 0-.3 .2 .21 .21 0 0 0 .3 .2M38 65.4a.21 .21 0 0 1 .2 .2 .21 .21 0 0 1-.2 .2M38 66a.2 .2 0 0 1 .2 .2 .2 .2 0 0 1-.2 .2M38 66.6a.21 .21 0 0 1 .2 .2 .21 .21 0 0 1-.2 .3M38 67.2a.21 .21 0 0 1 .2 .2 .21 .21 0 0 1-.2 .2M38 67.8a.21 .21 0 0 1 .2 .2 .21 .21 0 0 1-.2 .2M38 68.4a.21 .21 0 0 1 .2 .2 .21 .21 0 0 1-.2 .3M38 69a.21 .21 0 0 1 .2 .2 .21 .21 0 0 1-.2 .2M38 69.6a.21 .21 0 0 1 .2 .2 .21 .21 0 0 1-.2 .2M38 70.2a.21 .21 0 0 1 .2 .2 .21 .21 0 0 1-.2 .3M38 70.8a.21 .21 0 0 1 .2 .2 .21 .21 0 0 1-.2 .2M38 71.4a.21 .21 0 0 1 .2 .2 .21 .21 0 0 1-.2 .2"/>
<path d="M38 72a.21 .21 0 0 1 .2 .2 .21 .21 0 0 1-.2 .3M38 72.6a.21 .21 0 0 1 .2 .2 .21 .21 0 0 1-.2 .2M38 73.2a.21 .21 0 0 1 .2 .2 .21 .21 0 0 1-.2 .2M38 73.8a.21 .21 0 0 1 .2 .2 .21 .21 0 0 1-.2 .3M38 74.4a.21 .21 0 0 1 .2 .2 .21 .21 0 0 1-.2 .2M38 75a.21 .21 0 0 1 .2 .2 .21 .21 0 0 1-.2 .2M38 75.6a.2 .2 0 0 1 .2 .2 .2 .2 0 0 1-.2 .2M38.2 66.2h1.3M38.2 68h1.3M38.2 75.2h1.3M38.2 65.6h1.3M38.2 66.8h1.3"/>
<path d="M38.2 67.4h1.3M38.2 68.6h1.3M38.2 69.2h1.3M38.2 69.8h1.3M38.2 70.4h1.3M38.2 71h1.3M38.2 71.6h1.3M38.2 72.2h1.3M38.2 72.8h1.3M38.2 73.4h1.3M38.2 74h1.3M38.2 74.6h1.3"/>
<path d="M38.2 75.8h1.3M58.8 71h.9M59.2 70.4v.6M59.8 60.9h3.6M59.8 62.6h3.6M59.8 66.2h3.6M59.8 64.4h3.6M59.8 77h3.6M59.8 78.8h3.6M60.4 69.8h.8M61 75.2h5.4v9h-5.4zM61.5 69.8h.7"/>
<path d="M63.4 60.2l.6 .7-.6 .5zM63.4 62l.6 .6-.6 .6zM63.4 63.8l.6 .6-.6 .6zM63.4 65.6l.6 .6-.6 .6zM63.4 68v1.2M63.4 74v1.2M63.4 76.4l.6 .6-.6 .6zM63.4 78.2l.6 .6-.6 .6zM64 60.9h3.6M64 62.6h3.6M64 66.2h3.6M64 64.4h3.6"/>
<path d="M64 77h3.6M64 78.8h3.6M65.2 73.4h.8M66.3 73.4h.7M67.8 74.6h.9M68.2 74v.6M78 70.4h.9M78.4 69.8v.6M79 60.2h3.6M79 65.6h3.6M79 62h3.6M79 63.8h3.6"/>
<path d="M79.6 69.2h.7M80.7 69.2h.7M82.6 61.4l.6 .6-.6 .6zM82.6 63.2l.6 .6-.6 .6zM82.6 65l.6 .6-.6 .6zM82.6 67.4v1.2M83.2 60.2h3.6M83.2 65.6h3.6M83.2 62h3.6M83.2 63.8h3.6M112 73.4h.7M112 65h.7"/>
<path d="M113.1 73.4h.7M113.1 65h.7M113.9 61.4h1M113.9 69.2h1M113.9 77.6h1M114.2 66.8h.4v1.2h-.4zM114.2 75.2h.4v1.2h-.4zM114.4 60.2v1.2M114.4 66.2v.6M114.4 68v1.2M114.4 74.6v.6M114.4 76.4v1.2"/>
<path d="M142.1 69.8h.9M142.6 69.2v.6M143.2 61.4h3.6M143.2 75.8h3.6M143.2 65h3.6M143.2 77.6h3.6M143.2 63.2h3.6M143.2 79.4h3.6M143.8 68.6h.7M144.4 74h5.4v9h-5.4zM144.9 68.6h.7M146.8 60.9l.6 .5-.6 .6z"/>
<path d="M146.8 62.6l.6 .6-.6 .6zM146.8 64.4l.6 .6-.6 .6zM146.8 66.8v1.2M146.8 72.8v1.2M146.8 75.2l.6 .6-.6 .6zM146.8 77l.6 .6-.6 .6zM146.8 78.8l.6 .6-.6 .6zM147.4 61.4h3.6M147.4 75.8h3.6M147.4 65h3.6M147.4 77.6h3.6M147.4 63.2h3.6"/>
<path d="M147.4 79.4h3.6M148.6 72.2h.7M149.6 72.2h.8M151.1 73.4h.9M151.6 72.8v.6M161.3 69.2h.9M161.8 68.6v.6M162.4 60.9h3.6M162.4 62.6h3.6M162.4 64.4h3.6M163 68h.7M164 68h.8"/>
<path d="M166 60.2l.6 .7-.6 .5zM166 62l.6 .6-.6 .6zM166 63.8l.6 .6-.6 .6zM166 66.2v1.2M166.6 60.9h3.6M166.6 62.6h3.6M166.6 64.4h3.6M195.3 72.2h.8M195.3 63.8h.8M196.4 72.2h.7M196.4 63.8h.7M197.3 68h.9"/>
<path d="M197.3 60.2h.9M197.3 76.4h.9M197.5 74h.5v1.2h-.5zM197.5 65.6h.5v1.2h-.5zM197.7 65v.6M197.7 66.8v1.2M197.7 73.4v.6M197.7 75.2v1.2M224.9 68.6h.9M225.3 68v.6M225.9 60.2h3.6M225.9 74.6h3.6"/>
<path d="M225.9 76.4h3.6M225.9 62h3.6M225.9 63.8h3.6M225.9 78.2h3.6M226.5 67.4h.7M227.1 72.8h5.4v9h-5.4zM227.6 67.4h.7M229.5 61.4l.6 .6-.6 .6zM229.5 63.2l.6 .6-.6 .6zM229.5 65.6v1.2M229.5 71.6v1.2M229.5 74l.6 .6-.6 .6z"/>
<path d="M229.5 75.8l.6 .6-.6 .6zM229.5 77.6l.6 .6-.6 .6zM229.5 79.4l.6 .6-.6 .6zM230.1 60.2h3.6M230.1 74.6h3.6M230.1 76.4h3.6M230.1 62h3.6M230.1 63.8h3.6M230.1 78.2h3.6M231.3 71h.8M232.4 71h.7M233.9 72.2h.9"/>
<path d="M234.3 71.6v.6M244.1 68h.9M244.5 67.4v.6M245.1 61.4h3.6M245.1 63.2h3.6M245.7 66.8h.7M246.8 66.8h.7M248.7 60.9l.6 .5-.6 .6zM248.7 62.6l.6 .6-.6 .6zM248.7 65v1.2M249.3 61.4h3.6M249.3 63.2h3.6"/>
<path d="M278.1 62.6h.7M278.1 78.8h.7M278.1 71h.7M279.2 62.6h.7M279.2 78.8h.7M279.2 71h.7M280 75.2h.9M280 66.8h.9M280.3 64.4h.4v1.2h-.4zM280.3 72.8h.4v1.2h-.4zM280.5 63.8v.6M280.5 65.6v1.2"/>
<path d="M280.5 72.2v.6M280.5 74v1.2M9 94.4h.9M9 87.8h.9M9.2 92h.5v1.2h-.5zM9.2 85.4h.5v1.2h-.5zM9.2 98.6h.5v1.2h-.5zM9.5 84.8v.6M9.5 86.6v1.2M9.5 91.4v.6M9.5 93.2v1.2M9.5 98v.6"/>
<path d="M9.5 99.8v1.2M10.8 94.4h.9M10.8 87.8h.9M11 92h.5v1.2h-.5zM11 85.4h.5v1.2h-.5zM11 98.6h.5v1.2h-.5zM11.3 84.8v.6M11.3 86.6v1.2M11.3 91.4v.6M11.3 93.2v1.2M11.3 98v.6M11.3 99.8v1.2"/>
<path d="M12.6 94.4h.9M12.6 87.8h.9M12.8 92h.5v1.2h-.5zM12.8 85.4h.5v1.2h-.5zM12.8 98.6h.5v1.2h-.5zM13.1 84.8v.6M13.1 86.6v1.2M13.1 91.4v.6M13.1 93.2v1.2M13.1 98v.6M13.1 99.8v1.2M14.4 94.4h.9"/>
<path d="M14.4 87.8h.9M14.6 92h.5v1.2h-.5zM14.6 85.4h.5v1.2h-.5zM14.6 98.6h.5v1.2h-.5zM14.9 84.8v.6M14.9 86.6v1.2M14.9 91.4v.6M14.9 93.2v1.2M14.9 98v.6M14.9 99.8v1.2M32.6 84.8l.2-.1v.2zM32.6 86l.2-.1v.2z"/>
<path d="M32.6 87.2l.2-.1v.2zM32.6 88.4l.2-.1v.2zM32.6 89.6l.2-.1v.2zM32.6 90.8l.2-.1v.2zM32.6 92l.2-.1v.2zM32.6 93.2l.2-.1v.2zM32.6 94.4l.2-.1v.2zM32.6 95.6l.2-.1v.2zM32.6 96.8l.2-.1v.2zM32.6 98l.2-.1v.2zM32.6 99.2l.2-.1v.2zM33 84.7h1.1v.3h-1.1z"/>
<path d="M33 85.9h1.1v.3h-1.1zM33 87.1h1.1v.3h-1.1zM33 88.3h1.1v.3h-1.1zM33 89.5h1.1v.3h-1.1zM33 90.7h1.1v.3h-1.1zM33 91.9h1.1v.3h-1.1zM33 93.1h1.1v.3h-1.1zM33 94.3h1.1v.3h-1.1zM33 95.5h1.1v.3h-1.1zM33 96.7h1.1v.3h-1.1zM33 97.9h1.1v.3h-1.1zM33 99.1h1.1v.3h-1.1z"/>
<path d="M33.3 84.9l.1-.2v.2l.1-.2 .1 .2v-.2l.1 .2 .1-.2v.2l.1-.2v.2M33.3 86.1l.1-.2v.2l.1-.2 .1 .2v-.2l.1 .2 .1-.2v.2l.1-.2v.2M33.3 87.3l.1-.2v.2l.1-.2 .1 .2v-.2l.1 .2 .1-.2v.2l.1-.2v.2M33.3 88.5l.1-.2v.2l.1-.2 .1 .2v-.2l.1 .2 .1-.2v.2l.1-.2v.2M33.3 89.7l.1-.2v.2l.1-.2 .1 .2v-.2l.1 .2 .1-.2v.2l.1-.2v.2M33.3 90.9l.1-.2v.2l.1-.2 .1 .2v-.2l.1 .2 .1-.2v.2l.1-.2v.2M33.3 92.1l.1-.2v.2l.1-.2 .1 .2v-.2l.1 .2 .1-.2v.2l.1-.2v.2M33.3 93.3l.1-.2v.2l.1-.2 .1 .2v-.2l.1 .2 .1-.2v.2l.1-.2v.2M33.3 94.5l.1-.2v.2l.1-.2 .1 .2v-.2l.1 .2 .1-.2v.2l.1-.2v.2M33.3 95.7l.1-.2v.2l.1-.2 .1 .2v-.2l.1 .2 .1-.2v.2l.1-.2v.2M33.3 96.9l.1-.2v.2l.1-.2 .1 .2v-.2l.1 .2 .1-.2v.2l.1-.2v.2M33.3 98.1l.1-.2v.2l.1-.2 .1 .2v-.2l.1 .2 .1-.2v.2l.1-.2v.2"/>
<path d="M33.3 99.3l.1-.2v.2l.1-.2 .1 .2v-.2l.1 .2 .1-.2v.2l.1-.2v.2M34.1 84.8h.5M34.1 86h.5M34.1 87.2h.5M34.1 88.4h.5M34.1 89.6h.5M34.1 90.8h.5M34.1 92h.5M34.1 93.2h.5M34.1 94.4h.5M34.1 95.6h.5M34.1 96.8h.5"/>
<path d="M34.1 98h.5M34.1 99.2h.5M58.6 96.8h3.6M58.6 98.6h3.6M59.4 86.6h.9M59.8 82.4h3.6M59.8 80.6h3.6M59.8 95h5.4v9h-5.4zM59.8 86v.6M61 86h.7M62.1 86h.7M62.2 93.8v1.2"/>
<path d="M62.2 96.2l.6 .6-.6 .6zM62.2 98l.6 .6-.6 .6zM62.2 99.8l.6 .6-.6 .6zM62.8 96.8h3.6M62.8 98.6h3.6M63.4 80l.6 .6-.6 .6zM63.4 81.8l.6 .6-.6 .6zM63.4 84.2v1.2M64 82.4h3.6M64 80.6h3.6M64 93.2h.7M65.1 93.2h.7"/>
<path d="M66.6 94.4h.9M67 93.8v.6M77.8 98h3.6M77.8 96.2h3.6M77.8 99.8h3.6M79 94.4h5.4v9h-5.4zM81.4 93.2v1.2M81.4 95.6l.6 .6-.6 .6zM81.4 97.4l.6 .6-.6 .6zM81.4 99.2l.6 .6-.6 .6zM82 98h3.6M82 96.2h3.6"/>
<path d="M82 99.8h3.6M83.2 92.6h.7M84.3 92.6h.7M85.8 93.8h.9M86.2 93.2v.6M112 90.8h.7M112 81.2h.7M112 98.6h.7M113.1 90.8h.7M113.1 81.2h.7M113.1 98.6h.7M113.9 85.4h1"/>
<path d="M113.9 95h1M114.2 83h.4v1.2h-.4zM114.2 92.6h.4v1.2h-.4zM114.4 82.4v.6M114.4 84.2v1.2M114.4 92v.6M114.4 93.8v1.2M114.4 99.8v.6M142 95.6h3.6M142 99.2h3.6M142 97.4h3.6M142.7 85.4h.9"/>
<path d="M143.2 93.8h5.4v9h-5.4zM143.2 81.2h3.6M143.2 84.8v.6M144.4 84.8h.7M145.5 84.8h.7M145.6 92.6v1.2M145.6 95l.6 .6-.6 .6zM145.6 96.8l.6 .6-.6 .6zM145.6 98.6l.6 .6-.6 .6zM146.2 95.6h3.6M146.2 99.2h3.6M146.2 97.4h3.6"/>
<path d="M146.8 80.6l.6 .6-.6 .6zM146.8 83v1.2M147.4 92h.7M147.4 81.2h3.6M148.5 92h.7M149.9 93.2h.9M150.4 92.6v.6M161.2 96.8h3.6M161.2 98.6h3.6M161.2 95h3.6M162.4 93.2h5.4v9h-5.4zM164.8 98l.6 .6-.6 .6z"/>
<path d="M164.8 92v1.2M164.8 94.4l.6 .6-.6 .6zM164.8 96.2l.6 .6-.6 .6zM164.8 99.8l.6 .6-.6 .6zM165.4 96.8h3.6M165.4 98.6h3.6M165.4 95h3.6M166.6 91.4h.7M167.6 91.4h.8M169.1 92.6h.9M169.6 92v.6M195.3 89.6h.8"/>
<path d="M195.3 80h.8M195.3 97.4h.8M196.4 89.6h.7M196.4 80h.7M196.4 97.4h.7M197.3 84.2h.9M197.3 93.8h.9M197.5 99.2h.5v1.2h-.5zM197.5 81.8h.5v1.2h-.5zM197.5 91.4h.5v1.2h-.5zM197.7 81.2v.6M197.7 83v1.2"/>
<path d="M197.7 90.8v.6M197.7 92.6v1.2M197.7 98.6v.6M224.7 94.4h3.6M224.7 98h3.6M224.7 96.2h3.6M224.7 99.8h3.6M225.5 84.2h.9M225.9 92.6h5.4v9h-5.4zM225.9 80h3.6M225.9 83.6v.6M227.1 83.6h.7"/>
<path d="M228.2 83.6h.7M228.3 91.4v1.2M228.3 93.8l.6 .6-.6 .6zM228.3 95.6l.6 .6-.6 .6zM228.3 97.4l.6 .6-.6 .6zM228.3 99.2l.6 .6-.6 .6zM228.9 94.4h3.6M228.9 98h3.6M228.9 96.2h3.6M228.9 99.8h3.6M229.5 81.8v1.2M230.1 90.8h.7"/>
<path d="M230.1 80h3.6M231.2 90.8h.7M232.7 92h.9M233.1 91.4v.6M243.9 95.6h3.6M243.9 99.2h3.6M243.9 93.8h3.6M243.9 97.4h3.6M245.1 92h5.4v9h-5.4zM247.5 90.8v1.2M247.5 93.2l.6 .6-.6 .6zM247.5 95l.6 .6-.6 .6z"/>
<path d="M247.5 96.8l.6 .6-.6 .6zM247.5 98.6l.6 .6-.6 .6zM248.1 95.6h3.6M248.1 99.2h3.6M248.1 93.8h3.6M248.1 97.4h3.6M249.3 90.2h.7M250.4 90.2h.7M251.9 91.4h.9M252.3 90.8v.6M278.1 88.4h.7M278.1 96.2h.7"/>
<path d="M279.2 88.4h.7M279.2 96.2h.7M280 83h.9M280 92.6h.9M280.3 80.6h.4v1.2h-.4zM280.3 98h.4v1.2h-.4zM280.3 90.2h.4v1.2h-.4zM280.5 80v.6M280.5 81.8v1.2M280.5 89.6v.6M280.5 91.4v1.2M280.5 97.4v.6"/>
<path d="M280.5 99.2v1.2M9 113h.9M9 107h.9M9 119h.9M9 101h.9M9.2 116.6h.5v1.2h-.5zM9.2 110.6h.5v1.2h-.5zM9.2 104.6h.5v1.2h-.5zM9.5 104v.6M9.5 105.8v1.2M9.5 110v.6M9.5 111.8v1.2"/>
<path d="M9.5 116v.6M9.5 117.8v1.2M10.8 113h.9M10.8 107h.9M10.8 119h.9M10.8 101h.9M11 116.6h.5v1.2h-.5zM11 110.6h.5v1.2h-.5zM11 104.6h.5v1.2h-.5zM11.3 104v.6M11.3 105.8v1.2M11.3 110v.6"/>
<path d="M11.3 111.8v1.2M11.3 116v.6M11.3 117.8v1.2M12.6 113h.9M12.6 107h.9M12.6 119h.9M12.6 101h.9M12.8 116.6h.5v1.2h-.5zM12.8 110.6h.5v1.2h-.5zM12.8 104.6h.5v1.2h-.5zM13.1 104v.6M13.1 105.8v1.2"/>
<path d="M13.1 110v.6M13.1 111.8v1.2M13.1 116v.6M13.1 117.8v1.2M14.4 113h.9M14.4 107h.9M14.4 119h.9M14.4 101h.9M14.6 116.6h.5v1.2h-.5zM14.6 110.6h.5v1.2h-.5zM14.6 104.6h.5v1.2h-.5zM14.9 104v.6"/>
<path d="M14.9 105.8v1.2M14.9 110v.6M14.9 111.8v1.2M14.9 116v.6M14.9 117.8v1.2M32.6 100.4l.2-.1v.2zM32.6 101.6l.2-.1v.2zM32.6 102.8l.2-.1v.2zM32.6 104l.2-.1v.2zM32.6 105.2l.2-.1v.2zM32.6 106.4l.2-.1v.2zM32.6 107.6l.2-.1v.2z"/>
<path d="M32.6 108.8l.2-.1v.2zM32.6 110l.2-.1v.2zM32.6 111.2l.2-.1v.2zM32.6 112.4l.2-.1v.2zM32.6 113.6l.2-.1v.2zM32.6 114.8l.2-.1v.2zM32.6 116l.2-.1v.2zM32.6 117.2l.2-.1v.2zM32.6 118.4l.2-.1v.2zM32.6 119.6l.2-.1v.2zM33 100.3h1.1v.3h-1.1zM33 101.5h1.1v.3h-1.1z"/>
<path d="M33 102.7h1.1v.3h-1.1zM33 103.9h1.1v.3h-1.1zM33 105.1h1.1v.2h-1.1zM33 106.3h1.1v.3h-1.1zM33 107.5h1.1v.3h-1.1zM33 108.6h1.1v.3h-1.1zM33 109.9h1.1v.3h-1.1zM33 111.1h1.1v.3h-1.1zM33 112.2h1.1v.3h-1.1zM33 113.5h1.1v.2h-1.1zM33 114.6h1.1v.4h-1.1zM33 115.8h1.1v.3h-1.1z"/>
<path d="M33 117.1h1.1v.2h-1.1zM33 118.2h1.1v.4h-1.1zM33 119.4h1.1v.3h-1.1zM33.3 100.5l.1-.2v.2l.1-.2 .1 .2v-.2l.1 .2 .1-.2v.2l.1-.2v.2M33.3 101.7l.1-.2v.2l.1-.2 .1 .2v-.2l.1 .2 .1-.2v.2l.1-.2v.2M33.3 102.9l.1-.2v.2l.1-.2 .1 .2v-.2l.1 .2 .1-.2v.2l.1-.2v.2M33.3 104.1l.1-.2v.2l.1-.2 .1 .2v-.2l.1 .2 .1-.2v.2l.1-.2v.2M33.3 105.3l.1-.2v.2l.1-.2 .1 .2v-.2l.1 .2 .1-.2v.2l.1-.2v.2M33.3 106.5l.1-.2v.2l.1-.2 .1 .2v-.2l.1 .2 .1-.2v.2l.1-.2v.2M33.3 107.7l.1-.2v.2l.1-.2 .1 .2v-.2l.1 .2 .1-.2v.2l.1-.2v.2M33.3 108.9l.1-.2v.2l.1-.2 .1 .2v-.2l.1 .2 .1-.2v.2l.1-.2v.2M33.3 110.1l.1-.2v.2l.1-.2 .1 .2v-.2l.1 .2 .1-.2v.2l.1-.2v.2"/>
<path d="M33.3 111.3l.1-.2v.2l.1-.2 .1 .2v-.2l.1 .2 .1-.2v.2l.1-.2v.2M33.3 112.5l.1-.2v.2l.1-.2 .1 .2v-.2l.1 .2 .1-.2v.2l.1-.2v.2M33.3 113.7l.1-.2v.2l.1-.2 .1 .2v-.2l.1 .2 .1-.2v.2l.1-.2v.2M33.3 114.9l.1-.2v.2l.1-.2 .1 .2v-.2l.1 .2 .1-.2v.2l.1-.2v.2M33.3 116.1l.1-.2v.2l.1-.2 .1 .2v-.2l.1 .2 .1-.2v.2l.1-.2v.2M33.3 117.3l.1-.2v.2l.1-.2 .1 .2v-.2l.1 .2 .1-.2v.2l.1-.2v.2M33.3 118.5l.1-.2v.2l.1-.2 .1 .2v-.2l.1 .2 .1-.2v.2l.1-.2v.2M33.3 119.7l.1-.2v.2l.1-.2 .1 .2v-.2l.1 .2 .1-.2v.2l.1-.2v.2M34.1 100.4h.5M34.1 101.6h.5M34.1 102.8h.5M34.1 104h.5"/>
<path d="M34.1 105.2h.5M34.1 106.4h.5M34.1 107.6h.5M34.1 108.8h.5M34.1 110h.5M34.1 111.2h.5M34.1 112.4h.5M34.1 113.6h.5M34.1 114.8h.5M34.1 116h.5M34.1 117.2h.5M34.1 118.4h.5"/>
<path d="M34.1 119.6h.5M57.6 107h.9M58 106.4v.6M58.6 100.4h3.6M58.6 114.8h3.6M58.6 118.4h3.6M58.6 102.2h3.6M58.6 113h3.6M58.6 116.6h3.6M59.2 105.8h.7M59.8 111.2h5.4v9h-5.4zM60.3 105.8h.7"/>
<path d="M62.2 101.6l.6 .6-.6 .6zM62.2 104v1.2M62.2 110v1.2M62.2 112.4l.6 .6-.6 .6zM62.2 114.2l.6 .6-.6 .6zM62.2 116l.6 .6-.6 .6zM62.2 117.8l.6 .6-.6 .6zM62.8 100.4h3.6M62.8 114.8h3.6M62.8 118.4h3.6M62.8 102.2h3.6M62.8 113h3.6"/>
<path d="M62.8 116.6h3.6M64 109.4h.7M65.1 109.4h.7M66.6 110.6h.9M67 110v.6M76.8 106.4h.9M77.2 105.8v.6M77.8 101.6h3.6M78.4 105.2h.7M79.5 105.2h.7M81.4 101l.6 .6-.6 .6zM81.4 103.4v1.2"/>
<path d="M82 101.6h3.6M112 114.8h.7M112 107h.7M113.1 114.8h.7M113.1 107h.7M113.9 102.8h1M113.9 111.2h1M113.9 119h1M114.2 100.4h.4v1.2h-.4zM114.2 108.8h.4v1.2h-.4zM114.2 116.6h.4v1.2h-.4zM114.4 101.6v1.2"/>
<path d="M114.4 108.2v.6M114.4 110v1.2M114.4 116v.6M114.4 117.8v1.2M140.9 105.8h.9M141.4 105.2v.6M142 113.6h3.6M142 117.2h3.6M142 101h3.6M142 111.8h3.6M142 115.4h3.6M142.6 104.6h.7"/>
<path d="M143.2 110h5.4v9h-5.4zM143.7 104.6h.7M145.6 100.4l.6 .6-.6 .6zM145.6 102.8v1.2M145.6 108.8v1.2M145.6 111.2l.6 .6-.6 .6zM145.6 113l.6 .6-.6 .6zM145.6 114.8l.6 .6-.6 .6zM145.6 116.6l.6 .6-.6 .6zM145.6 119v1.2M146.2 113.6h3.6M146.2 117.2h3.6"/>
<path d="M146.2 101h3.6M146.2 111.8h3.6M146.2 115.4h3.6M147.4 108.2h.7M148.5 108.2h.7M149.9 109.4h.9M150.4 108.8v.6M160.1 105.2h.9M160.6 104.6v.6M161.2 100.4h3.6M161.8 104h.7M162.9 104h.7"/>
<path d="M164.8 102.2v1.2M165.4 100.4h3.6M195.3 113.6h.8M195.3 105.8h.8M196.4 113.6h.7M196.4 105.8h.7M197.3 101.6h.9M197.3 110h.9M197.3 117.8h.9M197.5 107.6h.5v1.2h-.5zM197.5 115.4h.5v1.2h-.5zM197.7 100.4v1.2"/>
<path d="M197.7 107v.6M197.7 108.8v1.2M197.7 114.8v.6M197.7 116.6v1.2M223.7 104.6h.9M224.1 104v.6M224.7 112.4h3.6M224.7 116h3.6M224.7 110.6h3.6M224.7 114.2h3.6M224.7 119.6v.6M225.3 103.4h.7"/>
<path d="M225.9 108.8h5.4v9h-5.4zM225.9 119.6h.8M226.4 103.4h.7M227 119.6h.7M228.3 101.6v1.2M228.3 107.6v1.2M228.3 110l.6 .6-.6 .6zM228.3 111.8l.6 .6-.6 .6zM228.3 113.6l.6 .6-.6 .6zM228.3 115.4l.6 .6-.6 .6zM228.3 117.8v1.2M228.9 112.4h3.6"/>
<path d="M228.9 116h3.6M228.9 110.6h3.6M228.9 114.2h3.6M230.1 107h.7M231.2 107h.7M232.7 108.2h.9M233.1 107.6v.6M242.9 104h.9M243.3 103.4v.6M244.5 102.8h.7M245.6 102.8h.7M247.5 101v1.2"/>
<path d="M278.1 112.4h.7M278.1 104.6h.7M279.2 112.4h.7M279.2 104.6h.7M280 100.4h.9M280 108.8h.9M280 116.6h.9M280.3 106.4h.4v1.2h-.4zM280.3 114.2h.4v1.2h-.4zM280.5 105.8v.6M280.5 107.6v1.2M280.5 113.6v.6"/>
<path d="M280.5 115.4v1.2M9 125h.9M9 131h.9M9.2 122.6h.5v1.2h-.5zM9.2 128.6h.5v1.2h-.5zM9.5 122v.6M9.5 123.8v1.2M9.5 128v.6M9.5 129.8v1.2M10.8 125h.9M10.8 131h.9M11 122.6h.5v1.2h-.5z"/>
<path d="M11 128.6h.5v1.2h-.5zM11.3 122v.6M11.3 123.8v1.2M11.3 128v.6M11.3 129.8v1.2M12.6 125h.9M12.6 131h.9M12.8 122.6h.5v1.2h-.5zM12.8 128.6h.5v1.2h-.5zM13.1 122v.6M13.1 123.8v1.2M13.1 128v.6"/>
<path d="M13.1 129.8v1.2M14.4 125h.9M14.4 131h.9M14.6 122.6h.5v1.2h-.5zM14.6 128.6h.5v1.2h-.5zM14.9 122v.6M14.9 123.8v1.2M14.9 128v.6M14.9 129.8v1.2M32.6 120.8l.2-.1v.2zM32.6 122l.2-.1v.2zM33 120.6h1.1v.3h-1.1z"/>
<path d="M33 121.8h1.1v.3h-1.1zM33.3 120.9l.1-.2v.2l.1-.2 .1 .2v-.2l.1 .2 .1-.2v.2l.1-.2v.2M33.3 122.1l.1-.2v.2l.1-.2 .1 .2v-.2l.1 .2 .1-.2v.2l.1-.2v.2M34.1 120.8h.5M34.1 122h.5M58 140v.6M58.2 122.6h.9M58.6 122v.6M58.6 135.8h3.6M58.6 130.4h3.6M58.6 132.2h3.6M58.6 134h3.6"/>
<path d="M59.2 139.4h.7M59.8 122h.8M59.8 128.6h5.4v9h-5.4zM60.3 139.4h.7M60.9 122h.7M62.2 120.2v1.2M62.2 127.4v1.2M62.2 129.8l.6 .6-.6 .6zM62.2 131.6l.6 .6-.6 .6zM62.2 133.4l.6 .6-.6 .6zM62.2 135.2l.6 .6-.6 .6zM62.2 137.6v1.2"/>
<path d="M62.8 135.8h3.6M62.8 130.4h3.6M62.8 132.2h3.6M62.8 134h3.6M64 126.8h.7M65.1 126.8h.7M66.6 128h.9M67 127.4v.6M76.8 140h.9M77.2 139.4v.6M77.8 129.8h3.6M77.8 131.6h3.6"/>
<path d="M77.8 135.2h3.6M77.8 133.4h3.6M78.4 138.8h.7M79 128h5.4v9h-5.4zM79.5 138.8h.7M81.4 126.8v1.2M81.4 129.2l.6 .6-.6 .6zM81.4 131l.6 .6-.6 .6zM81.4 132.8l.6 .6-.6 .6zM81.4 134.6l.6 .6-.6 .6zM81.4 137v1.2M82 129.8h3.6"/>
<path d="M82 131.6h3.6M82 135.2h3.6M82 133.4h3.6M83.2 126.2h.7M84.3 126.2h.7M85.8 127.4h.9M86.2 126.8v.6M112 125h.7M112 132.8h.7M113.1 125h.7M113.1 132.8h.7M113.9 129.2h1"/>
<path d="M113.9 137h1M114.2 126.8h.4v1.2h-.4zM114.2 134.6h.4v1.2h-.4zM114.4 126.2v.6M114.4 128v1.2M114.4 134v.6M114.4 135.8v1.2M140.9 139.4h.9M141.4 138.8v.6M141.5 121.4h.9M142 129.2h3.6M142 132.8h3.6"/>
<path d="M142 134.6h3.6M142 120.8v.6M142 131h3.6M142.6 138.2h.7M143.2 120.8h.7M143.2 127.4h5.4v9h-5.4zM143.7 138.2h.7M144.3 120.8h.7M145.6 126.2v1.2M145.6 128.6l.6 .6-.6 .6zM145.6 130.4l.6 .6-.6 .6zM145.6 132.2l.6 .6-.6 .6z"/>
<path d="M145.6 134l.6 .6-.6 .6zM145.6 136.4v1.2M146.2 129.2h3.6M146.2 132.8h3.6M146.2 134.6h3.6M146.2 131h3.6M147.4 125.6h.7M148.5 125.6h.7M149.9 126.8h.9M150.4 126.2v.6M160.1 138.8h.9M160.6 138.2v.6"/>
<path d="M161.2 130.4h3.6M161.2 132.2h3.6M161.2 134h3.6M161.2 128.6h3.6M161.8 137.6h.7M162.4 126.8h5.4v9h-5.4zM162.9 137.6h.7M164.8 125.6v1.2M164.8 128l.6 .6-.6 .6zM164.8 129.8l.6 .6-.6 .6zM164.8 131.6l.6 .6-.6 .6zM164.8 133.4l.6 .6-.6 .6z"/>
<path d="M164.8 135.8v1.2M165.4 130.4h3.6M165.4 132.2h3.6M165.4 134h3.6M165.4 128.6h3.6M166.6 125h.7M167.6 125h.8M169.1 126.2h.9M169.6 125.6v.6M195.3 131.6h.8M195.3 140h.8M195.3 123.8h.8"/>
<path d="M196.4 131.6h.7M196.4 140h.7M196.4 123.8h.7M197.3 128h.9M197.3 135.8h.9M197.5 125.6h.5v1.2h-.5zM197.5 133.4h.5v1.2h-.5zM197.7 125v.6M197.7 126.8v1.2M197.7 132.8v.6M197.7 134.6v1.2M224.3 120.2h.9"/>
<path d="M57.6 140.6h.9M58.2 156.2h.9M58.6 155.6v.6M58.6 152h3.6M58.6 146.6h3.6M58.6 148.4h3.6M58.6 150.2h3.6M59.8 144.8h5.4v9h-5.4zM59.8 155.6h.8M60.9 155.6h.7M62.2 143.6v1.2M62.2 146l.6 .6-.6 .6z"/>
<path d="M62.2 147.8l.6 .6-.6 .6zM62.2 149.6l.6 .6-.6 .6zM62.2 151.4l.6 .6-.6 .6zM62.2 153.8v1.2M62.8 152h3.6M62.8 146.6h3.6M62.8 148.4h3.6M62.8 150.2h3.6M64 143h.7M65.1 143h.7M66.6 144.2h.9M67 143.6v.6"/>
<path d="M112 141.2h.7M112 149h.7M113.1 141.2h.7M113.1 149h.7M113.9 145.4h1M113.9 153.2h1M114.2 143h.4v1.2h-.4zM114.2 150.8h.4v1.2h-.4zM114.4 142.4v.6M114.4 144.2v1.2M114.4 150.2v.6M114.4 152v1.2"/>
<path d="M141.5 155h.9M142 145.4h3.6M142 149h3.6M142 150.8h3.6M142 154.4v.6M142 147.2h3.6M143.2 143.6h5.4v9h-5.4zM143.2 154.4h.7M144.3 154.4h.7M145.6 142.4v1.2M145.6 144.8l.6 .6-.6 .6zM145.6 146.6l.6 .6-.6 .6z"/>
<path d="M145.6 148.4l.6 .6-.6 .6zM145.6 150.2l.6 .6-.6 .6zM145.6 152.6v1.2M146.2 145.4h3.6M146.2 149h3.6M146.2 150.8h3.6M146.2 147.2h3.6M147.4 141.8h.7M148.5 141.8h.7M149.9 143h.9M150.4 142.4v.6M195.3 147.8h.8"/>
<path d="M196.4 147.8h.7M197.3 144.2h.9M197.3 152h.9M197.5 141.8h.5v1.2h-.5zM197.5 149.6h.5v1.2h-.5zM197.7 141.2v.6M197.7 143v1.2M197.7 149v.6M197.7 150.8v1.2"/>
</g>
<g fill="#800000" stroke="#800000" stroke-width=".13">
<path d="M113 56.8h.1v.9h-.1z"/>
<path d="M112.7 56.8h.1v.9h-.1z"/>
<path d="M32.8 84.7h.2v.2h-.2z"/>
<path d="M32.8 85.9h.2v.2h-.2z"/>
<path d="M32.8 87.1h.2v.2h-.2z"/>
<path d="M32.8 88.3h.2v.2h-.2z"/>
<path d="M32.8 89.5h.2v.2h-.2z"/>
<path d="M32.8 90.7h.2v.2h-.2z"/>
<path d="M32.8 91.9h.2v.2h-.2z"/>
<path d="M32.8 93.1h.2v.2h-.2z"/>
<path d="M32.8 94.3h.2v.2h-.2z"/>
<path d="M32.8 95.5h.2v.2h-.2z"/>
<path d="M32.8 96.7h.2v.2h-.2z"/>
<path d="M32.8 97.9h.2v.2h-.2z"/>
<path d="M32.8 99.1h.2v.2h-.2z"/>
<path d="M32.8 100.3h.2v.2h-.2z"/>
<path d="M32.8 101.5h.2v.2h-.2z"/>
<path d="M32.8 102.7h.2v.2h-.2z"/>
<path d="M32.8 103.9h.2v.2h-.2z"/>
<path d="M32.8 105.1h.2v.2h-.2z"/>
<path d="M32.8 106.3h.2v.2h-.2z"/>
<path d="M32.8 107.5h.2v.2h-.2z"/>
<path d="M32.8 108.7h.2v.2h-.2z"/>
<path d="M32.8 109.9h.2v.2h-.2z"/>
<path d="M32.8 111.1h.2v.2h-.2z"/>
<path d="M32.8 112.3h.2v.2h-.2z"/>
<path d="M32.8 113.5h.2v.2h-.2z"/>
<path d="M32.8 114.7h.2v.2h-.2z"/>
<path d="M32.8 115.9h.2v.2h-.2z"/>
<path d="M32.8 117.1h.2v.2h-.2z"/>
<path d="M32.8 118.3h.2v.2h-.2z"/>
<path d="M32.8 119.5h.2v.2h-.2z"/>
<path d="M32.8 120.7h.2v.2h-.2z"/>
<path d="M32.8 121.9h.2v.2h-.2z"/>
<path d="M113 64.6h.1v.9h-.1z"/>
<path d="M112.7 64.6h.1v.9h-.1z"/>
<path d="M66.2 56.8h.1v.9h-.1z"/>
<path d="M66 56.8h.1v.9h-.1z"/>
<path d="M66.2 72.9h.1v1h-.1z"/>
<path d="M66 72.9h.1v1h-.1z"/>
<path d="M61.7 85.5h.2v1h-.2z"/>
<path d="M62 85.5h.1v1h-.1z"/>
<path d="M61.2 69.3h.1v1h-.1z"/>
<path d="M61.4 69.3h.1v1h-.1z"/>
<path d="M85.4 56.2h.1v.9h-.1z"/>
<path d="M85.1 56.2h.2v.9h-.2z"/>
<path d="M80.3 68.7h.2v1h-.2z"/>
<path d="M80.6 68.7h.1v1h-.1z"/>
<path d="M113 72.9h.1v1h-.1z"/>
<path d="M112.7 72.9h.1v1h-.1z"/>
<path d="M113 80.7h.1v1h-.1z"/>
<path d="M112.7 80.7h.1v1h-.1z"/>
<path d="M65 92.7h.1v1h-.1z"/>
<path d="M64.7 92.7h.2v1h-.2z"/>
<path d="M65 108.9h.1v1h-.1z"/>
<path d="M64.7 108.9h.2v1h-.2z"/>
<path d="M60.6 121.5h.1v1h-.1z"/>
<path d="M60.8 121.5h.1v1h-.1z"/>
<path d="M59.9 105.3h.2v1h-.2z"/>
<path d="M60.2 105.3h.1v1h-.1z"/>
<path d="M84.2 92.1h.1v1h-.1z"/>
<path d="M83.9 92.1h.2v1h-.2z"/>
<path d="M79.1 104.7h.2v1h-.2z"/>
<path d="M79.4 104.7h.1v1h-.1z"/>
<path d="M113 90.3h.1v1h-.1z"/>
<path d="M112.7 90.3h.1v1h-.1z"/>
<path d="M113 98.1h.1v1h-.1z"/>
<path d="M112.7 98.1h.1v1h-.1z"/>
<path d="M113 106.5h.1v1h-.1z"/>
<path d="M112.7 106.5h.1v1h-.1z"/>
<path d="M113 114.3h.1v1h-.1z"/>
<path d="M112.7 114.3h.1v1h-.1z"/>
<path d="M113 124.5h.1v1h-.1z"/>
<path d="M112.7 124.5h.1v1h-.1z"/>
<path d="M113 132.3h.1v1h-.1z"/>
<path d="M112.7 132.3h.1v1h-.1z"/>
<path d="M113 140.7h.1v1h-.1z"/>
<path d="M112.7 140.7h.1v1h-.1z"/>
<path d="M113 148.5h.1v1h-.1z"/>
<path d="M112.7 148.5h.1v1h-.1z"/>
<path d="M65 126.3h.1v1h-.1z"/>
<path d="M64.7 126.3h.2v1h-.2z"/>
<path d="M65 142.5h.1v1h-.1z"/>
<path d="M64.7 142.5h.2v1h-.2z"/>
<path d="M60.6 155.1h.1v.9h-.1z"/>
<path d="M60.8 155.1h.1v.9h-.1z"/>
<path d="M59.9 138.9h.2v1h-.2z"/>
<path d="M60.2 138.9h.1v1h-.1z"/>
<path d="M84.2 125.7h.1v1h-.1z"/>
<path d="M83.9 125.7h.2v1h-.2z"/>
<path d="M79.1 138.3h.2v1h-.2z"/>
<path d="M79.4 138.3h.1v1h-.1z"/>
<path d="M196.3 55.6h.1v.9h-.1z"/>
<path d="M196.1 55.6h.1v.9h-.1z"/>
<path d="M196.3 63.4h.1v.9h-.1z"/>
<path d="M196.1 63.4h.1v.9h-.1z"/>
<path d="M149.5 55.6h.2v.9h-.2z"/>
<path d="M149.3 55.6h.1v.9h-.1z"/>
<path d="M149.5 71.8h.2v.9h-.2z"/>
<path d="M149.3 71.8h.1v.9h-.1z"/>
<path d="M145.1 84.3h.1v1h-.1z"/>
<path d="M145.3 84.3h.2v1h-.2z"/>
<path d="M144.5 68.2h.1v.9h-.1z"/>
<path d="M144.7 68.2h.2v.9h-.2z"/>
<path d="M168.7 55h.1v.9h-.1z"/>
<path d="M168.5 55h.1v.9h-.1z"/>
<path d="M163.7 67.5h.1v1h-.1z"/>
<path d="M163.9 67.5h.1v1h-.1z"/>
<path d="M196.3 71.8h.1v.9h-.1z"/>
<path d="M196.1 71.8h.1v.9h-.1z"/>
<path d="M196.3 79.5h.1v1h-.1z"/>
<path d="M196.1 79.5h.1v1h-.1z"/>
<path d="M148.3 91.5h.2v1h-.2z"/>
<path d="M148.1 91.5h.1v1h-.1z"/>
<path d="M148.3 107.7h.2v1h-.2z"/>
<path d="M148.1 107.7h.1v1h-.1z"/>
<path d="M143.9 120.3h.1v1h-.1z"/>
<path d="M144.1 120.3h.2v1h-.2z"/>
<path d="M143.3 104.1h.1v1h-.1z"/>
<path d="M143.5 104.1h.2v1h-.2z"/>
<path d="M167.5 90.9h.1v1h-.1z"/>
<path d="M167.3 90.9h.1v1h-.1z"/>
<path d="M162.5 103.5h.1v1h-.1z"/>
<path d="M162.7 103.5h.2v1h-.2z"/>
<path d="M196.3 89.1h.1v1h-.1z"/>
<path d="M196.1 89.1h.1v1h-.1z"/>
<path d="M196.3 96.9h.1v1h-.1z"/>
<path d="M196.1 96.9h.1v1h-.1z"/>
<path d="M196.3 105.3h.1v1h-.1z"/>
<path d="M196.1 105.3h.1v1h-.1z"/>
<path d="M196.3 113.1h.1v1h-.1z"/>
<path d="M196.1 113.1h.1v1h-.1z"/>
<path d="M196.3 123.3h.1v1h-.1z"/>
<path d="M196.1 123.3h.1v1h-.1z"/>
<path d="M196.3 131.1h.1v1h-.1z"/>
<path d="M196.1 131.1h.1v1h-.1z"/>
<path d="M196.3 139.5h.1v1h-.1z"/>
<path d="M196.1 139.5h.1v1h-.1z"/>
<path d="M196.3 147.3h.1v1h-.1z"/>
<path d="M196.1 147.3h.1v1h-.1z"/>
<path d="M148.3 125.1h.2v1h-.2z"/>
<path d="M148.1 125.1h.1v1h-.1z"/>
<path d="M148.3 141.3h.2v1h-.2z"/>
<path d="M148.1 141.3h.1v1h-.1z"/>
<path d="M143.9 153.9h.1v1h-.1z"/>
<path d="M144.1 153.9h.2v1h-.2z"/>
<path d="M143.3 137.7h.1v1h-.1z"/>
<path d="M143.5 137.7h.2v1h-.2z"/>
<path d="M167.5 124.5h.1v1h-.1z"/>
<path d="M167.3 124.5h.1v1h-.1z"/>
<path d="M162.5 137.1h.1v1h-.1z"/>
<path d="M162.7 137.1h.2v1h-.2z"/>
<path d="M279 54.4h.2v.9h-.2z"/>
<path d="M278.8 54.4h.1v.9h-.1z"/>
<path d="M279 62.1h.2v1h-.2z"/>
<path d="M278.8 62.1h.1v1h-.1z"/>
<path d="M232.3 54.4h.1v.9h-.1z"/>
<path d="M232 54.4h.2v.9h-.2z"/>
<path d="M232.3 70.5h.1v1h-.1z"/>
<path d="M232 70.5h.2v1h-.2z"/>
<path d="M227.8 83.1h.2v1h-.2z"/>
<path d="M228.1 83.1h.1v1h-.1z"/>
<path d="M227.2 67h.2v.9h-.2z"/>
<path d="M227.5 67h.1v.9h-.1z"/>
<path d="M251.5 53.8h.1v.9h-.1z"/>
<path d="M251.2 53.8h.2v.9h-.2z"/>
<path d="M246.4 66.4h.1v.9h-.1z"/>
<path d="M246.7 66.4h.1v.9h-.1z"/>
<path d="M279 70.5h.2v1h-.2z"/>
<path d="M278.8 70.5h.1v1h-.1z"/>
<path d="M279 78.3h.2v1h-.2z"/>
<path d="M278.8 78.3h.1v1h-.1z"/>
<path d="M231.1 90.3h.1v1h-.1z"/>
<path d="M230.8 90.3h.2v1h-.2z"/>
<path d="M231.1 106.5h.1v1h-.1z"/>
<path d="M230.8 106.5h.2v1h-.2z"/>
<path d="M226.7 119.1h.1v1h-.1z"/>
<path d="M226.9 119.1h.1v1h-.1z"/>
<path d="M226 102.9h.2v1h-.2z"/>
<path d="M226.3 102.9h.1v1h-.1z"/>
<path d="M250.3 89.7h.1v1h-.1z"/>
<path d="M250 89.7h.1v1h-.1z"/>
<path d="M245.2 102.3h.2v1h-.2z"/>
<path d="M245.5 102.3h.1v1h-.1z"/>
<path d="M279 87.9h.2v1h-.2z"/>
<path d="M278.8 87.9h.1v1h-.1z"/>
<path d="M279 95.7h.2v1h-.2z"/>
<path d="M278.8 95.7h.1v1h-.1z"/>
<path d="M279 104.1h.2v1h-.2z"/>
<path d="M278.8 104.1h.1v1h-.1z"/>
<path d="M279 111.9h.2v1h-.2z"/>
<path d="M278.8 111.9h.1v1h-.1z"/>
</g>
<g fill="none" stroke="#800000" stroke-width=".15">
<path d="M22.6 65.6h.4M22.6 66.8h.4M22.6 66.2h.4M22.6 68h.4M22.6 69.2h.4M22.6 67.4h.4M22.6 70.4h.4M22.6 71.6h.4M22.6 68.6h.4M22.6 72.8h.4M22.6 74h.4M22.6 69.8h.4"/>
<path d="M22.6 75.2h.4M22.6 71h.4M22.6 72.2h.4M22.6 73.4h.4M22.6 74.6h.4M22.6 75.8h.4M23.6 65.6h.3M23.6 66.8h.3M23.6 66.2h.3M23.6 68h.3M23.6 69.2h.3M23.6 67.4h.3"/>
<path d="M23.6 70.4h.3M23.6 71.6h.3M23.6 68.6h.3M23.6 72.8h.3M23.6 74h.3M23.6 69.8h.3M23.6 75.2h.3M23.6 76.4h.3M23.6 71h.3M23.6 72.2h.3M23.6 73.4h.3M23.6 74.6h.3"/>
<path d="M23.6 75.8h.3"/>
</g>
<g fill="none" stroke="#008000" stroke-width=".13">
<path d="M63.4 57.3h1.8M63.4 56v1.8M67 57.3h1.2v.5M82.6 56.6h1.8M82.6 55.5v1.8M86.2 56.6h1.2v.7M108.4 57.3h3.6M113.8 57.3h4.8M114.4 57.3v1.1M141.4 59.6h1.8M146.8 56h1.8M146.8 54.8v1.8"/>
<path d="M150.4 56h1.2v.6M151 59.6h2.4M160 59.1h2.4M166 55.5h1.8M166 54.3v1.7M169.6 55.5h1.2v.5M170.2 59.1h4.1M191.7 56h3.6M197.1 56h4.9M197.7 56v1.3M224.1 58.4h1.8M229.5 54.8h1.8"/>
<path d="M229.5 53.7v1.8M233.1 54.8h1.2v.7M233.7 58.4h2.4M242.7 59.6h2.4M242.7 57.8h2.4M248.7 54.3h1.8M248.7 53v1.8M252.3 54.3h1.2v.5M252.9 59.6h4.2M252.9 57.8h4.2M274.5 54.8h3.6M279.9 54.8h4.8"/>
<path d="M280.5 54.8v1.2M19.7 65.6h1.8M19.7 66.2h1.8M19.7 69.8h1.8M19.7 69.2h1.8M19.7 72.2h1.8M19.7 68.6h1.8M19.7 68h1.8M19.7 71h1.8M19.7 67.4h1.8M19.7 66.8h1.8M19.7 70.4h1.8"/>
<path d="M19.7 71.6h1.8M19.7 72.8h1.8M25.1 65.6h1.8M25.1 66.2h1.8M25.1 73.4h1.8M25.1 69.8h1.8M25.1 69.2h1.8M25.1 72.2h1.8M25.1 68.6h1.8M25.1 68h1.8M25.1 71h1.8M25.1 67.4h1.8"/>
<path d="M25.1 66.8h1.8M25.1 70.4h1.8M25.1 71.6h1.8M25.1 72.8h1.8M25.1 75.8h1.8M25.1 74h1.8M25.1 74.6h1.8M25.1 75.2h1.8M25.1 76.4h1.8M34.6 65.6h1.3M34.6 66.2h1.3M34.6 73.4h1.3"/>
<path d="M34.6 69.8h1.3M34.6 69.2h1.3M34.6 72.2h1.3M34.6 68.6h1.3M34.6 68h1.3M34.6 71h1.3M34.6 67.4h1.3M34.6 66.8h1.3M34.6 70.4h1.3M34.6 71.6h1.3M34.6 72.8h1.3M34.6 75.8h1.3"/>
<path d="M34.6 74h1.3M34.6 74.6h1.3M34.6 75.2h1.3M34.6 76.4h1.3M39.5 65.6h1.1M39.5 66.2h1.1M39.5 69.8h1.1M39.5 69.2h1.1M39.5 72.2h1.1M39.5 68.6h1.1M39.5 68h1.1M39.5 71h1.1"/>
<path d="M39.5 67.4h1.1M39.5 66.8h1.1M39.5 70.4h1.1M39.5 71.6h1.1M39.5 72.8h1.1M58 60.9h1.8M58 77h1.8M58 66.2h1.8M58 78.8h1.8M58 62.6h1.8M58 64.4h1.8M60.4 69.8h-1.2v.6"/>
<path d="M62.2 69.8h1.2M63.4 73.4h1.8M63.4 69.2v1.2M63.4 72.8v1.2M67 73.4h1.2v.6M67.6 60.9h2.4M67.6 77h2.4M67.6 66.2h2.4M67.6 78.8h1.8M67.6 62.6h1.8M67.6 64.4h2.4M76.6 65.6h2.4"/>
<path d="M76.6 60.2h2.4M76.6 62h2.4M77.2 63.8h1.8M79.6 69.2h-1.2v.6M81.4 69.2h1.2M82.6 68.6v1.2M86.8 65.6h4.2M86.8 63.8h4.2M86.8 60.2h4.2M86.8 62h4.2M108.4 65h3.6M109.6 73.4h2.4"/>
<path d="M113.8 73.4h4.2M113.8 65h4.8M114.4 65v1.2M114.4 73.4v1.2M141.4 75.8h1.8M141.4 77.6h1.8M141.4 61.4h1.8M141.4 79.4h1.8M141.4 63.2h1.8M141.4 65h1.8M143.8 68.6h-1.2v.6M145.6 68.6h1.2"/>
<path d="M146.8 72.2h1.8M146.8 68v1.2M146.8 71.6v1.2M150.4 72.2h1.2v.6M151 75.8h2.4M151 77.6h1.8M151 61.4h1.8M151 79.4h1.8M151 63.2h2.4M151 65h2.4M160 60.9h2.4M160 64.4h2.4"/>
<path d="M160.6 62.6h1.8M163 68h-1.2v.6M164.8 68h1.2M166 67.4v1.2M170.2 60.9h4.1M170.2 62.6h4.1M170.2 64.4h4.1M191.7 72.2h3.6M191.7 63.8h3.6M197.1 72.2h4.2M197.1 63.8h4.9M197.7 63.8v1.2"/>
<path d="M197.7 72.2v1.2M224.1 63.8h1.8M224.1 74.6h1.8M224.1 76.4h1.8M224.1 60.2h1.8M224.1 78.2h1.8M224.1 62h1.8M226.5 67.4h-1.2v.6M228.3 67.4h1.2M229.5 71h1.8M229.5 66.8v1.2M229.5 70.4v1.2"/>
<path d="M233.1 71h1.2v.6M233.7 63.8h2.4M233.7 74.6h2.4M233.7 76.4h1.8M233.7 60.2h1.8M233.7 78.2h1.8M233.7 62h2.4M242.7 63.2h2.4M243.3 61.4h1.8M245.7 66.8h-1.2v.6M247.5 66.8h1.2M248.7 66.2v1.2"/>
<path d="M252.9 61.4h4.2M252.9 63.2h4.2M274.5 62.6h3.6M275.7 71h2.4M275.7 78.8h2.4M279.9 71h4.2M279.9 78.8h4.2M279.9 62.6h4.8M280.5 62.6v1.2M280.5 71v1.2M280.5 78.8v1.2M9.5 83.6v1.2"/>
<path d="M9.5 90.2v1.2M9.5 96.8v1.2M11.3 83.6v1.2M11.3 90.2v1.2M11.3 96.8v1.2M13.1 83.6v1.2M13.1 90.2v1.2M13.1 96.8v1.2M14.9 83.6v1.2M14.9 90.2v1.2M14.9 96.8v1.2M34.6 84.8h1.8"/>
<path d="M34.6 86h1.8M34.6 93.2h1.8M34.6 92h1.8M34.6 90.8h1.8M34.6 87.2h1.8M34.6 88.4h1.8M34.6 89.6h1.8M34.6 96.8h1.8M34.6 94.4h1.8M34.6 95.6h1.8M34.6 98h1.8M34.6 99.2h1.8"/>
<path d="M56.8 96.8h1.8M56.8 98.6h1.8M58 80.6h1.8M58 82.4h1.8M59.8 86h1.2M62.2 93.2h1.8M62.2 92v1.8M62.8 86h.6M63.4 85.4v1.2M65.8 93.2h1.2v.6M66.4 96.8h1.2M66.4 98.6h1.2"/>
<path d="M67.6 80.6h1.8M67.6 82.4h1.8M74.8 98h3M74.8 96.2h3M75.4 99.8h2.4M81.4 92.6h1.8M81.4 91.4v1.8M85 92.6h1.2v.6M85.6 99.8h3.6M85.6 98h4.2M85.6 96.2h4.2M107.8 90.8h4.2"/>
<path d="M108.4 98.6h3.6M109.6 81.2h2.4M113.8 90.8h3M113.8 98.6h3.6M113.8 81.2h4.2M114.4 81.2v1.2M114.4 90.8v1.2M114.4 98.6v1.2M140.2 95.6h1.8M140.2 99.2h1.8M140.2 97.4h1.8M141.4 81.2h1.8"/>
<path d="M143.2 84.8h1.2M145.6 92h1.8M145.6 90.8v1.8M146.2 84.8h.6M146.8 84.2v1.2M149.2 92h1.2v.6M149.8 95.6h1.2M149.8 99.2h1.2M149.8 97.4h1.2M151 81.2h1.8M158.2 96.8h3M158.2 95h3"/>
<path d="M158.8 98.6h2.4M164.8 91.4h1.8M164.8 90.2v1.8M168.4 91.4h1.2v.6M169 96.8h4.2M169 98.6h3.6M169 95h4.2M191.7 89.6h3.6M191.7 97.4h3.6M191.7 80h3.6M197.1 89.6h3.1M197.1 97.4h3.6"/>
<path d="M197.1 80h4.2M197.7 80v1.2M197.7 89.6v1.2M197.7 97.4v1.2M222.9 99.8h1.8M222.9 94.4h1.8M222.9 98h1.8M222.9 96.2h1.8M224.1 80h1.8M225.9 83.6h1.2M228.3 90.8h1.8M228.3 89.6v1.8"/>
<path d="M228.9 83.6h.6M229.5 83v1.2M231.9 90.8h1.2v.6M232.5 99.8h1.2M232.5 94.4h1.2M232.5 98h1.2M232.5 96.2h1.2M233.7 80h1.8M240.9 95.6h3M240.9 93.8h3M241.5 99.2h2.4M241.5 97.4h2.4"/>
<path d="M247.5 90.2h1.8M247.5 89v1.8M251.1 90.2h1.2v.6M251.7 95.6h4.2M251.7 99.2h4.2M251.7 97.4h3.6M251.7 93.8h4.2M273.9 88.4h4.2M274.5 96.2h3.6M279.9 88.4h3M279.9 96.2h3.6M280.5 88.4v1.2"/>
<path d="M280.5 96.2v1.2M9.5 102.8v1.2M9.5 108.8v1.2M9.5 114.8v1.2M11.3 102.8v1.2M11.3 108.8v1.2M11.3 114.8v1.2M13.1 102.8v1.2M13.1 108.8v1.2M13.1 114.8v1.2M14.9 102.8v1.2M14.9 108.8v1.2"/>
<path d="M14.9 114.8v1.2M34.6 105.2h1.8M34.6 104h1.8M34.6 119.6h1.8M34.6 102.8h1.8M34.6 114.8h1.8M34.6 118.4h1.8M34.6 101.6h1.8M34.6 100.4h1.8M34.6 113.6h1.8M34.6 106.4h1.8M34.6 107.6h1.8"/>
<path d="M34.6 117.2h1.8M34.6 108.8h1.8M34.6 110h1.8M34.6 111.2h1.8M34.6 112.4h1.8M34.6 116h1.8M56.2 113h2.4M56.2 114.8h2.4M56.2 116.6h2.4M56.2 118.4h2.4M56.8 100.4h1.8M56.8 102.2h1.8"/>
<path d="M59.2 105.8h-1.2v.6M61 105.8h1.2M62.2 109.4h1.8M62.2 105.2v1.2M62.2 108.8v1.2M65.8 109.4h1.2v.6M66.4 113h1.8M66.4 114.8h1.8M66.4 116.6h1.8M66.4 118.4h1.8M66.4 100.4h1.2M66.4 102.2h1.2"/>
<path d="M75.4 101.6h2.4M78.4 105.2h-1.2v.6M80.2 105.2h1.2M81.4 104.6v1.2M85.6 101.6h4.2M108.4 107h3.6M108.4 114.8h3.6M113.8 107h3.6M113.8 114.8h3.6M114.4 107v1.2M114.4 114.8v1.2M139.6 111.8h2.4"/>
<path d="M139.6 113.6h2.4M139.6 115.4h2.4M139.6 117.2h2.4M140.2 101h1.8M142.6 104.6h-1.2v.6M144.4 104.6h1.2M145.6 108.2h1.8M145.6 104v1.2M145.6 107.6v1.2M149.2 108.2h1.2v.6M149.8 111.8h1.8M149.8 113.6h1.8"/>
<path d="M149.8 115.4h1.8M149.8 117.2h1.8M149.8 101h1.2M158.8 100.4h2.4M161.8 104h-1.2v.6M163.6 104h1.2M164.8 103.4v1.2M169 100.4h4.2M191.7 105.8h3.6M191.7 113.6h3.6M197.1 105.8h3.6M197.1 113.6h3.6"/>
<path d="M197.7 105.8v1.2M197.7 113.6v1.2M222.3 112.4h2.4M222.3 116h2.4M222.3 110.6h2.4M222.3 114.2h2.4M224.7 119.6h1.2M225.3 103.4h-1.2v.6M227.1 103.4h1.2M227.7 119.6h.6M228.3 107h1.8M228.3 102.8v1.2"/>
<path d="M228.3 106.4v1.2M228.3 119v1.2M231.9 107h1.2v.6M232.5 112.4h4.2M232.5 116h3.6M232.5 110.6h4.2M232.5 114.2h3.6M244.5 102.8h-1.2v.6M246.3 102.8h1.2M247.5 102.2v1.2M274.5 104.6h3.6M274.5 112.4h3.6"/>
<path d="M279.9 104.6h3.6M279.9 112.4h3.6M280.5 104.6v1.2M280.5 112.4v1.2M9.5 120.8v1.2M9.5 126.8v1.2M11.3 120.8v1.2M11.3 126.8v1.2M13.1 120.8v1.2M13.1 126.8v1.2M14.9 120.8v1.2M14.9 126.8v1.2"/>
<path d="M34.6 122h1.8M34.6 120.8h1.8M55.6 134h3M55.6 135.8h3M56.2 130.4h2.4M56.2 132.2h2.4M58.6 122h1.2M59.2 139.4h-1.2v.6M61 139.4h1.2M61.6 122h.6M62.2 126.8h1.8M62.2 121.4v1.2"/>
<path d="M62.2 125.6v1.8M62.2 138.8v1.2M65.8 126.8h1.2v.6M66.4 130.4h2.4M66.4 132.2h2.4M66.4 134h1.8M66.4 135.8h2.4M74.8 133.4h3M74.8 135.2h3M74.8 129.8h3M74.8 131.6h3M78.4 138.8h-1.2v.6"/>
<path d="M80.2 138.8h1.2M81.4 126.2h1.8M81.4 125v1.8M81.4 138.2v1.2M85 126.2h1.2v.6M85.6 133.4h3.6M85.6 135.2h3.6M85.6 129.8h3.6M85.6 131.6h3.6M107.8 125h4.2M108.4 132.8h3.6M113.8 125h3"/>
<path d="M113.8 132.8h3.6M114.4 125v1.2M114.4 132.8v1.2M139 134.6h3M139 132.8h3M139.6 129.2h2.4M139.6 131h2.4M142 120.8h1.2M142.6 138.2h-1.2v.6M144.4 138.2h1.2M145 120.8h.6M145.6 125.6h1.8"/>
<path d="M145.6 120.2v1.2M145.6 124.4v1.8M145.6 137.6v1.2M149.2 125.6h1.2v.6M149.8 129.2h2.4M149.8 131h2.4M149.8 134.6h2.4M149.8 132.8h1.8M158.2 130.4h3M158.2 132.2h3M158.2 134h3M158.2 128.6h3"/>
<path d="M161.8 137.6h-1.2v.6M163.6 137.6h1.2M164.8 125h1.8M164.8 123.8v1.8M164.8 137v1.2M168.4 125h1.2v.6M169 130.4h3.6M169 132.2h3.6M169 134h3.6M169 128.6h3.6M191.7 131.6h3.6M191.7 123.8h3.6"/>
<path d="M191.7 140h3.6M197.1 131.6h3.6M197.1 123.8h3.1M197.1 140h3.6M197.7 123.8v1.2M197.7 131.6v1.2M197.7 140v1.2M55 148.4h3.6M55.6 146.6h3M55.6 150.2h3M56.2 152h2.4M58.6 155.6h1.2"/>
<path d="M62.2 143h1.8M62.2 142.4v1.2M62.2 155l-.6 .6M65.8 143h1.2v.6M66.4 146.6h3M66.4 148.4h3M66.4 150.2h3M66.4 152h3M108.4 149h3.6M108.4 141.2h3.6M113.8 149h3.6M113.8 141.2h3.6"/>
<path d="M114.4 141.2v1.2M114.4 149v1.2M138.4 147.2h3.6M139 145.4h3M139 149h3M139.6 150.8h2.4M142 154.4h1.2M145.6 141.8h1.8M145.6 141.2v1.2M145.6 153.8l-.6 .6M149.2 141.8h1.2v.6M149.8 145.4h3"/>
<path d="M149.8 147.2h3M149.8 149h3M149.8 150.8h3M191.7 147.8h3.6M197.1 147.8h3.6M197.7 147.8v1.2"/>
</g>
<g fill="#008000" stroke="#008000" stroke-width=".13">
<circle cx="114.4" cy="57.3" r=".13"/>
<circle cx="114.4" cy="65" r=".13"/>
<circle cx="63.4" cy="57.3" r=".13"/>
<circle cx="63.4" cy="73.4" r=".13"/>
<circle cx="82.6" cy="56.6" r=".13"/>
<circle cx="62.2" cy="93.2" r=".13"/>
<circle cx="62.2" cy="109.4" r=".13"/>
<circle cx="81.4" cy="92.6" r=".13"/>
<circle cx="62.2" cy="126.8" r=".13"/>
<circle cx="62.2" cy="143" r=".13"/>
<circle cx="81.4" cy="126.2" r=".13"/>
<circle cx="146.8" cy="56" r=".13"/>
<circle cx="146.8" cy="72.2" r=".13"/>
<circle cx="166" cy="55.5" r=".13"/>
<circle cx="145.6" cy="92" r=".13"/>
<circle cx="145.6" cy="108.2" r=".13"/>
<circle cx="164.8" cy="91.4" r=".13"/>
<circle cx="145.6" cy="125.6" r=".13"/>
<circle cx="145.6" cy="141.8" r=".13"/>
<circle cx="164.8" cy="125" r=".13"/>
<circle cx="229.5" cy="54.8" r=".13"/>
<circle cx="229.5" cy="71" r=".13"/>
<circle cx="248.7" cy="54.3" r=".13"/>
<circle cx="228.3" cy="90.8" r=".13"/>
<circle cx="228.3" cy="107" r=".13"/>
<circle cx="247.5" cy="90.2" r=".13"/>
<circle cx="63.4" cy="69.8" r=".13"/>
<circle cx="63.4" cy="86" r=".13"/>
<circle cx="82.6" cy="69.2" r=".13"/>
<circle cx="62.2" cy="105.8" r=".13"/>
<circle cx="62.2" cy="122" r=".13"/>
<circle cx="81.4" cy="105.2" r=".13"/>
<circle cx="62.2" cy="139.4" r=".13"/>
<circle cx="81.4" cy="138.8" r=".13"/>
<circle cx="146.8" cy="68.6" r=".13"/>
<circle cx="146.8" cy="84.8" r=".13"/>
<circle cx="166" cy="68" r=".13"/>
<circle cx="145.6" cy="104.6" r=".13"/>
<circle cx="145.6" cy="120.8" r=".13"/>
<circle cx="164.8" cy="104" r=".13"/>
<circle cx="145.6" cy="138.2" r=".13"/>
<circle cx="164.8" cy="137.6" r=".13"/>
<circle cx="229.5" cy="67.4" r=".13"/>
<circle cx="229.5" cy="83.6" r=".13"/>
<circle cx="248.7" cy="66.8" r=".13"/>
<circle cx="228.3" cy="103.4" r=".13"/>
<circle cx="228.3" cy="119.6" r=".13"/>
<circle cx="247.5" cy="102.8" r=".13"/>
<circle cx="114.4" cy="81.2" r=".13"/>
<circle cx="114.4" cy="73.4" r=".13"/>
<circle cx="114.4" cy="98.6" r=".13"/>
<circle cx="114.4" cy="114.8" r=".13"/>
<circle cx="114.4" cy="107" r=".13"/>
<circle cx="114.4" cy="90.8" r=".13"/>
<circle cx="114.4" cy="125" r=".13"/>
<circle cx="114.4" cy="132.8" r=".13"/>
<circle cx="114.4" cy="141.2" r=".13"/>
<circle cx="114.4" cy="149" r=".13"/>
<circle cx="197.7" cy="56" r=".13"/>
<circle cx="197.7" cy="63.8" r=".13"/>
<circle cx="197.7" cy="72.2" r=".13"/>
<circle cx="197.7" cy="80" r=".13"/>
<circle cx="197.7" cy="89.6" r=".13"/>
<circle cx="197.7" cy="97.4" r=".13"/>
<circle cx="197.7" cy="105.8" r=".13"/>
<circle cx="197.7" cy="113.6" r=".13"/>
<circle cx="197.7" cy="123.8" r=".13"/>
<circle cx="197.7" cy="131.6" r=".13"/>
<circle cx="197.7" cy="140" r=".13"/>
<circle cx="197.7" cy="147.8" r=".13"/>
<circle cx="280.5" cy="54.8" r=".13"/>
<circle cx="280.5" cy="62.6" r=".13"/>
<circle cx="280.5" cy="71" r=".13"/>
<circle cx="280.5" cy="78.8" r=".13"/>
<circle cx="280.5" cy="88.4" r=".13"/>
<circle cx="280.5" cy="96.2" r=".13"/>
<circle cx="280.5" cy="104.6" r=".13"/>
<circle cx="280.5" cy="112.4" r=".13"/>
</g>
<use href="#words"/>
</svg>
